VERSION 5.7 ;
  NOWIREEXTENSIONATPIN ON ;
  DIVIDERCHAR "/" ;
  BUSBITCHARS "[]" ;
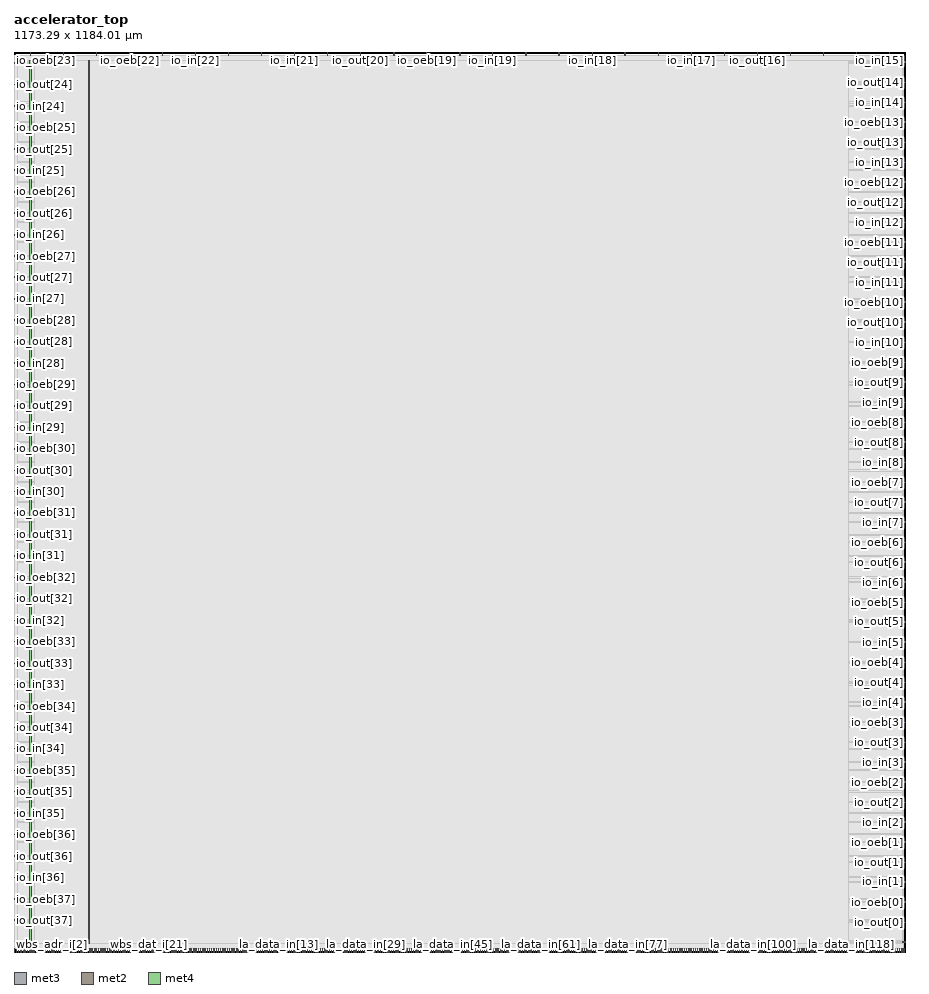
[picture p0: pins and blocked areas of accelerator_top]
MACRO accelerator_top
  CLASS BLOCK ;
  FOREIGN accelerator_top ;
  ORIGIN 0.000 0.000 ;
  SIZE 1173.290 BY 1184.010 ;
  PIN io_in[0]
    DIRECTION INPUT ;
    PORT
      LAYER met3 ;
        RECT 1169.290 12.960 1173.290 13.560 ;
    END
  END io_in[0]
  PIN io_in[10]
    DIRECTION INPUT ;
    PORT
      LAYER met3 ;
        RECT 1169.290 801.760 1173.290 802.360 ;
    END
  END io_in[10]
  PIN io_in[11]
    DIRECTION INPUT ;
    PORT
      LAYER met3 ;
        RECT 1169.290 880.640 1173.290 881.240 ;
    END
  END io_in[11]
  PIN io_in[12]
    DIRECTION INPUT ;
    PORT
      LAYER met3 ;
        RECT 1169.290 959.520 1173.290 960.120 ;
    END
  END io_in[12]
  PIN io_in[13]
    DIRECTION INPUT ;
    PORT
      LAYER met3 ;
        RECT 1169.290 1038.400 1173.290 1039.000 ;
    END
  END io_in[13]
  PIN io_in[14]
    DIRECTION INPUT ;
    PORT
      LAYER met3 ;
        RECT 1169.290 1117.280 1173.290 1117.880 ;
    END
  END io_in[14]
  PIN io_in[15]
    DIRECTION INPUT ;
    PORT
      LAYER met2 ;
        RECT 1151.470 1180.010 1151.750 1184.010 ;
    END
  END io_in[15]
  PIN io_in[16]
    DIRECTION INPUT ;
    PORT
      LAYER met2 ;
        RECT 1021.290 1180.010 1021.570 1184.010 ;
    END
  END io_in[16]
  PIN io_in[17]
    DIRECTION INPUT ;
    PORT
      LAYER met2 ;
        RECT 890.650 1180.010 890.930 1184.010 ;
    END
  END io_in[17]
  PIN io_in[18]
    DIRECTION INPUT ;
    PORT
      LAYER met2 ;
        RECT 760.470 1180.010 760.750 1184.010 ;
    END
  END io_in[18]
  PIN io_in[19]
    DIRECTION INPUT ;
    PORT
      LAYER met2 ;
        RECT 629.830 1180.010 630.110 1184.010 ;
    END
  END io_in[19]
  PIN io_in[1]
    DIRECTION INPUT ;
    PORT
      LAYER met3 ;
        RECT 1169.290 91.840 1173.290 92.440 ;
    END
  END io_in[1]
  PIN io_in[20]
    DIRECTION INPUT ;
    PORT
      LAYER met2 ;
        RECT 499.650 1180.010 499.930 1184.010 ;
    END
  END io_in[20]
  PIN io_in[21]
    DIRECTION INPUT ;
    PORT
      LAYER met2 ;
        RECT 369.010 1180.010 369.290 1184.010 ;
    END
  END io_in[21]
  PIN io_in[22]
    DIRECTION INPUT ;
    PORT
      LAYER met2 ;
        RECT 238.830 1180.010 239.110 1184.010 ;
    END
  END io_in[22]
  PIN io_in[23]
    DIRECTION INPUT ;
    PORT
      LAYER met2 ;
        RECT 108.190 1180.010 108.470 1184.010 ;
    END
  END io_in[23]
  PIN io_in[24]
    DIRECTION INPUT ;
    PORT
      LAYER met3 ;
        RECT 0.000 1112.520 4.000 1113.120 ;
    END
  END io_in[24]
  PIN io_in[25]
    DIRECTION INPUT ;
    PORT
      LAYER met3 ;
        RECT 0.000 1028.200 4.000 1028.800 ;
    END
  END io_in[25]
  PIN io_in[26]
    DIRECTION INPUT ;
    PORT
      LAYER met3 ;
        RECT 0.000 943.200 4.000 943.800 ;
    END
  END io_in[26]
  PIN io_in[27]
    DIRECTION INPUT ;
    PORT
      LAYER met3 ;
        RECT 0.000 858.880 4.000 859.480 ;
    END
  END io_in[27]
  PIN io_in[28]
    DIRECTION INPUT ;
    PORT
      LAYER met3 ;
        RECT 0.000 774.560 4.000 775.160 ;
    END
  END io_in[28]
  PIN io_in[29]
    DIRECTION INPUT ;
    PORT
      LAYER met3 ;
        RECT 0.000 689.560 4.000 690.160 ;
    END
  END io_in[29]
  PIN io_in[2]
    DIRECTION INPUT ;
    PORT
      LAYER met3 ;
        RECT 1169.290 170.720 1173.290 171.320 ;
    END
  END io_in[2]
  PIN io_in[30]
    DIRECTION INPUT ;
    PORT
      LAYER met3 ;
        RECT 0.000 605.240 4.000 605.840 ;
    END
  END io_in[30]
  PIN io_in[31]
    DIRECTION INPUT ;
    PORT
      LAYER met3 ;
        RECT 0.000 520.920 4.000 521.520 ;
    END
  END io_in[31]
  PIN io_in[32]
    DIRECTION INPUT ;
    PORT
      LAYER met3 ;
        RECT 0.000 435.920 4.000 436.520 ;
    END
  END io_in[32]
  PIN io_in[33]
    DIRECTION INPUT ;
    PORT
      LAYER met3 ;
        RECT 0.000 351.600 4.000 352.200 ;
    END
  END io_in[33]
  PIN io_in[34]
    DIRECTION INPUT ;
    PORT
      LAYER met3 ;
        RECT 0.000 267.280 4.000 267.880 ;
    END
  END io_in[34]
  PIN io_in[35]
    DIRECTION INPUT ;
    PORT
      LAYER met3 ;
        RECT 0.000 182.280 4.000 182.880 ;
    END
  END io_in[35]
  PIN io_in[36]
    DIRECTION INPUT ;
    PORT
      LAYER met3 ;
        RECT 0.000 97.960 4.000 98.560 ;
    END
  END io_in[36]
  PIN io_in[37]
    DIRECTION INPUT ;
    PORT
      LAYER met3 ;
        RECT 0.000 13.640 4.000 14.240 ;
    END
  END io_in[37]
  PIN io_in[3]
    DIRECTION INPUT ;
    PORT
      LAYER met3 ;
        RECT 1169.290 249.600 1173.290 250.200 ;
    END
  END io_in[3]
  PIN io_in[4]
    DIRECTION INPUT ;
    PORT
      LAYER met3 ;
        RECT 1169.290 328.480 1173.290 329.080 ;
    END
  END io_in[4]
  PIN io_in[5]
    DIRECTION INPUT ;
    PORT
      LAYER met3 ;
        RECT 1169.290 407.360 1173.290 407.960 ;
    END
  END io_in[5]
  PIN io_in[6]
    DIRECTION INPUT ;
    PORT
      LAYER met3 ;
        RECT 1169.290 486.240 1173.290 486.840 ;
    END
  END io_in[6]
  PIN io_in[7]
    DIRECTION INPUT ;
    PORT
      LAYER met3 ;
        RECT 1169.290 565.120 1173.290 565.720 ;
    END
  END io_in[7]
  PIN io_in[8]
    DIRECTION INPUT ;
    PORT
      LAYER met3 ;
        RECT 1169.290 644.000 1173.290 644.600 ;
    END
  END io_in[8]
  PIN io_in[9]
    DIRECTION INPUT ;
    PORT
      LAYER met3 ;
        RECT 1169.290 722.880 1173.290 723.480 ;
    END
  END io_in[9]
  PIN io_oeb[0]
    DIRECTION OUTPUT TRISTATE ;
    PORT
      LAYER met3 ;
        RECT 1169.290 65.320 1173.290 65.920 ;
    END
  END io_oeb[0]
  PIN io_oeb[10]
    DIRECTION OUTPUT TRISTATE ;
    PORT
      LAYER met3 ;
        RECT 1169.290 854.800 1173.290 855.400 ;
    END
  END io_oeb[10]
  PIN io_oeb[11]
    DIRECTION OUTPUT TRISTATE ;
    PORT
      LAYER met3 ;
        RECT 1169.290 933.680 1173.290 934.280 ;
    END
  END io_oeb[11]
  PIN io_oeb[12]
    DIRECTION OUTPUT TRISTATE ;
    PORT
      LAYER met3 ;
        RECT 1169.290 1012.560 1173.290 1013.160 ;
    END
  END io_oeb[12]
  PIN io_oeb[13]
    DIRECTION OUTPUT TRISTATE ;
    PORT
      LAYER met3 ;
        RECT 1169.290 1091.440 1173.290 1092.040 ;
    END
  END io_oeb[13]
  PIN io_oeb[14]
    DIRECTION OUTPUT TRISTATE ;
    PORT
      LAYER met3 ;
        RECT 1169.290 1170.320 1173.290 1170.920 ;
    END
  END io_oeb[14]
  PIN io_oeb[15]
    DIRECTION OUTPUT TRISTATE ;
    PORT
      LAYER met2 ;
        RECT 1064.530 1180.010 1064.810 1184.010 ;
    END
  END io_oeb[15]
  PIN io_oeb[16]
    DIRECTION OUTPUT TRISTATE ;
    PORT
      LAYER met2 ;
        RECT 934.350 1180.010 934.630 1184.010 ;
    END
  END io_oeb[16]
  PIN io_oeb[17]
    DIRECTION OUTPUT TRISTATE ;
    PORT
      LAYER met2 ;
        RECT 803.710 1180.010 803.990 1184.010 ;
    END
  END io_oeb[17]
  PIN io_oeb[18]
    DIRECTION OUTPUT TRISTATE ;
    PORT
      LAYER met2 ;
        RECT 673.530 1180.010 673.810 1184.010 ;
    END
  END io_oeb[18]
  PIN io_oeb[19]
    DIRECTION OUTPUT TRISTATE ;
    PORT
      LAYER met2 ;
        RECT 542.890 1180.010 543.170 1184.010 ;
    END
  END io_oeb[19]
  PIN io_oeb[1]
    DIRECTION OUTPUT TRISTATE ;
    PORT
      LAYER met3 ;
        RECT 1169.290 144.200 1173.290 144.800 ;
    END
  END io_oeb[1]
  PIN io_oeb[20]
    DIRECTION OUTPUT TRISTATE ;
    PORT
      LAYER met2 ;
        RECT 412.710 1180.010 412.990 1184.010 ;
    END
  END io_oeb[20]
  PIN io_oeb[21]
    DIRECTION OUTPUT TRISTATE ;
    PORT
      LAYER met2 ;
        RECT 282.070 1180.010 282.350 1184.010 ;
    END
  END io_oeb[21]
  PIN io_oeb[22]
    DIRECTION OUTPUT TRISTATE ;
    PORT
      LAYER met2 ;
        RECT 151.890 1180.010 152.170 1184.010 ;
    END
  END io_oeb[22]
  PIN io_oeb[23]
    DIRECTION OUTPUT TRISTATE ;
    PORT
      LAYER met2 ;
        RECT 21.710 1180.010 21.990 1184.010 ;
    END
  END io_oeb[23]
  PIN io_oeb[24]
    DIRECTION OUTPUT TRISTATE ;
    PORT
      LAYER met3 ;
        RECT 0.000 1168.960 4.000 1169.560 ;
    END
  END io_oeb[24]
  PIN io_oeb[25]
    DIRECTION OUTPUT TRISTATE ;
    PORT
      LAYER met3 ;
        RECT 0.000 1084.640 4.000 1085.240 ;
    END
  END io_oeb[25]
  PIN io_oeb[26]
    DIRECTION OUTPUT TRISTATE ;
    PORT
      LAYER met3 ;
        RECT 0.000 999.640 4.000 1000.240 ;
    END
  END io_oeb[26]
  PIN io_oeb[27]
    DIRECTION OUTPUT TRISTATE ;
    PORT
      LAYER met3 ;
        RECT 0.000 915.320 4.000 915.920 ;
    END
  END io_oeb[27]
  PIN io_oeb[28]
    DIRECTION OUTPUT TRISTATE ;
    PORT
      LAYER met3 ;
        RECT 0.000 831.000 4.000 831.600 ;
    END
  END io_oeb[28]
  PIN io_oeb[29]
    DIRECTION OUTPUT TRISTATE ;
    PORT
      LAYER met3 ;
        RECT 0.000 746.000 4.000 746.600 ;
    END
  END io_oeb[29]
  PIN io_oeb[2]
    DIRECTION OUTPUT TRISTATE ;
    PORT
      LAYER met3 ;
        RECT 1169.290 223.080 1173.290 223.680 ;
    END
  END io_oeb[2]
  PIN io_oeb[30]
    DIRECTION OUTPUT TRISTATE ;
    PORT
      LAYER met3 ;
        RECT 0.000 661.680 4.000 662.280 ;
    END
  END io_oeb[30]
  PIN io_oeb[31]
    DIRECTION OUTPUT TRISTATE ;
    PORT
      LAYER met3 ;
        RECT 0.000 577.360 4.000 577.960 ;
    END
  END io_oeb[31]
  PIN io_oeb[32]
    DIRECTION OUTPUT TRISTATE ;
    PORT
      LAYER met3 ;
        RECT 0.000 492.360 4.000 492.960 ;
    END
  END io_oeb[32]
  PIN io_oeb[33]
    DIRECTION OUTPUT TRISTATE ;
    PORT
      LAYER met3 ;
        RECT 0.000 408.040 4.000 408.640 ;
    END
  END io_oeb[33]
  PIN io_oeb[34]
    DIRECTION OUTPUT TRISTATE ;
    PORT
      LAYER met3 ;
        RECT 0.000 323.040 4.000 323.640 ;
    END
  END io_oeb[34]
  PIN io_oeb[35]
    DIRECTION OUTPUT TRISTATE ;
    PORT
      LAYER met3 ;
        RECT 0.000 238.720 4.000 239.320 ;
    END
  END io_oeb[35]
  PIN io_oeb[36]
    DIRECTION OUTPUT TRISTATE ;
    PORT
      LAYER met3 ;
        RECT 0.000 154.400 4.000 155.000 ;
    END
  END io_oeb[36]
  PIN io_oeb[37]
    DIRECTION OUTPUT TRISTATE ;
    PORT
      LAYER met3 ;
        RECT 0.000 69.400 4.000 70.000 ;
    END
  END io_oeb[37]
  PIN io_oeb[3]
    DIRECTION OUTPUT TRISTATE ;
    PORT
      LAYER met3 ;
        RECT 1169.290 301.960 1173.290 302.560 ;
    END
  END io_oeb[3]
  PIN io_oeb[4]
    DIRECTION OUTPUT TRISTATE ;
    PORT
      LAYER met3 ;
        RECT 1169.290 380.840 1173.290 381.440 ;
    END
  END io_oeb[4]
  PIN io_oeb[5]
    DIRECTION OUTPUT TRISTATE ;
    PORT
      LAYER met3 ;
        RECT 1169.290 459.720 1173.290 460.320 ;
    END
  END io_oeb[5]
  PIN io_oeb[6]
    DIRECTION OUTPUT TRISTATE ;
    PORT
      LAYER met3 ;
        RECT 1169.290 538.600 1173.290 539.200 ;
    END
  END io_oeb[6]
  PIN io_oeb[7]
    DIRECTION OUTPUT TRISTATE ;
    PORT
      LAYER met3 ;
        RECT 1169.290 617.480 1173.290 618.080 ;
    END
  END io_oeb[7]
  PIN io_oeb[8]
    DIRECTION OUTPUT TRISTATE ;
    PORT
      LAYER met3 ;
        RECT 1169.290 696.360 1173.290 696.960 ;
    END
  END io_oeb[8]
  PIN io_oeb[9]
    DIRECTION OUTPUT TRISTATE ;
    PORT
      LAYER met3 ;
        RECT 1169.290 775.240 1173.290 775.840 ;
    END
  END io_oeb[9]
  PIN io_out[0]
    DIRECTION OUTPUT TRISTATE ;
    PORT
      LAYER met3 ;
        RECT 1169.290 38.800 1173.290 39.400 ;
    END
  END io_out[0]
  PIN io_out[10]
    DIRECTION OUTPUT TRISTATE ;
    PORT
      LAYER met3 ;
        RECT 1169.290 828.280 1173.290 828.880 ;
    END
  END io_out[10]
  PIN io_out[11]
    DIRECTION OUTPUT TRISTATE ;
    PORT
      LAYER met3 ;
        RECT 1169.290 907.160 1173.290 907.760 ;
    END
  END io_out[11]
  PIN io_out[12]
    DIRECTION OUTPUT TRISTATE ;
    PORT
      LAYER met3 ;
        RECT 1169.290 986.040 1173.290 986.640 ;
    END
  END io_out[12]
  PIN io_out[13]
    DIRECTION OUTPUT TRISTATE ;
    PORT
      LAYER met3 ;
        RECT 1169.290 1064.920 1173.290 1065.520 ;
    END
  END io_out[13]
  PIN io_out[14]
    DIRECTION OUTPUT TRISTATE ;
    PORT
      LAYER met3 ;
        RECT 1169.290 1143.800 1173.290 1144.400 ;
    END
  END io_out[14]
  PIN io_out[15]
    DIRECTION OUTPUT TRISTATE ;
    PORT
      LAYER met2 ;
        RECT 1108.230 1180.010 1108.510 1184.010 ;
    END
  END io_out[15]
  PIN io_out[16]
    DIRECTION OUTPUT TRISTATE ;
    PORT
      LAYER met2 ;
        RECT 977.590 1180.010 977.870 1184.010 ;
    END
  END io_out[16]
  PIN io_out[17]
    DIRECTION OUTPUT TRISTATE ;
    PORT
      LAYER met2 ;
        RECT 847.410 1180.010 847.690 1184.010 ;
    END
  END io_out[17]
  PIN io_out[18]
    DIRECTION OUTPUT TRISTATE ;
    PORT
      LAYER met2 ;
        RECT 716.770 1180.010 717.050 1184.010 ;
    END
  END io_out[18]
  PIN io_out[19]
    DIRECTION OUTPUT TRISTATE ;
    PORT
      LAYER met2 ;
        RECT 586.590 1180.010 586.870 1184.010 ;
    END
  END io_out[19]
  PIN io_out[1]
    DIRECTION OUTPUT TRISTATE ;
    PORT
      LAYER met3 ;
        RECT 1169.290 117.680 1173.290 118.280 ;
    END
  END io_out[1]
  PIN io_out[20]
    DIRECTION OUTPUT TRISTATE ;
    PORT
      LAYER met2 ;
        RECT 455.950 1180.010 456.230 1184.010 ;
    END
  END io_out[20]
  PIN io_out[21]
    DIRECTION OUTPUT TRISTATE ;
    PORT
      LAYER met2 ;
        RECT 325.770 1180.010 326.050 1184.010 ;
    END
  END io_out[21]
  PIN io_out[22]
    DIRECTION OUTPUT TRISTATE ;
    PORT
      LAYER met2 ;
        RECT 195.130 1180.010 195.410 1184.010 ;
    END
  END io_out[22]
  PIN io_out[23]
    DIRECTION OUTPUT TRISTATE ;
    PORT
      LAYER met2 ;
        RECT 64.950 1180.010 65.230 1184.010 ;
    END
  END io_out[23]
  PIN io_out[24]
    DIRECTION OUTPUT TRISTATE ;
    PORT
      LAYER met3 ;
        RECT 0.000 1141.080 4.000 1141.680 ;
    END
  END io_out[24]
  PIN io_out[25]
    DIRECTION OUTPUT TRISTATE ;
    PORT
      LAYER met3 ;
        RECT 0.000 1056.080 4.000 1056.680 ;
    END
  END io_out[25]
  PIN io_out[26]
    DIRECTION OUTPUT TRISTATE ;
    PORT
      LAYER met3 ;
        RECT 0.000 971.760 4.000 972.360 ;
    END
  END io_out[26]
  PIN io_out[27]
    DIRECTION OUTPUT TRISTATE ;
    PORT
      LAYER met3 ;
        RECT 0.000 887.440 4.000 888.040 ;
    END
  END io_out[27]
  PIN io_out[28]
    DIRECTION OUTPUT TRISTATE ;
    PORT
      LAYER met3 ;
        RECT 0.000 802.440 4.000 803.040 ;
    END
  END io_out[28]
  PIN io_out[29]
    DIRECTION OUTPUT TRISTATE ;
    PORT
      LAYER met3 ;
        RECT 0.000 718.120 4.000 718.720 ;
    END
  END io_out[29]
  PIN io_out[2]
    DIRECTION OUTPUT TRISTATE ;
    PORT
      LAYER met3 ;
        RECT 1169.290 196.560 1173.290 197.160 ;
    END
  END io_out[2]
  PIN io_out[30]
    DIRECTION OUTPUT TRISTATE ;
    PORT
      LAYER met3 ;
        RECT 0.000 633.120 4.000 633.720 ;
    END
  END io_out[30]
  PIN io_out[31]
    DIRECTION OUTPUT TRISTATE ;
    PORT
      LAYER met3 ;
        RECT 0.000 548.800 4.000 549.400 ;
    END
  END io_out[31]
  PIN io_out[32]
    DIRECTION OUTPUT TRISTATE ;
    PORT
      LAYER met3 ;
        RECT 0.000 464.480 4.000 465.080 ;
    END
  END io_out[32]
  PIN io_out[33]
    DIRECTION OUTPUT TRISTATE ;
    PORT
      LAYER met3 ;
        RECT 0.000 379.480 4.000 380.080 ;
    END
  END io_out[33]
  PIN io_out[34]
    DIRECTION OUTPUT TRISTATE ;
    PORT
      LAYER met3 ;
        RECT 0.000 295.160 4.000 295.760 ;
    END
  END io_out[34]
  PIN io_out[35]
    DIRECTION OUTPUT TRISTATE ;
    PORT
      LAYER met3 ;
        RECT 0.000 210.840 4.000 211.440 ;
    END
  END io_out[35]
  PIN io_out[36]
    DIRECTION OUTPUT TRISTATE ;
    PORT
      LAYER met3 ;
        RECT 0.000 125.840 4.000 126.440 ;
    END
  END io_out[36]
  PIN io_out[37]
    DIRECTION OUTPUT TRISTATE ;
    PORT
      LAYER met3 ;
        RECT 0.000 41.520 4.000 42.120 ;
    END
  END io_out[37]
  PIN io_out[3]
    DIRECTION OUTPUT TRISTATE ;
    PORT
      LAYER met3 ;
        RECT 1169.290 275.440 1173.290 276.040 ;
    END
  END io_out[3]
  PIN io_out[4]
    DIRECTION OUTPUT TRISTATE ;
    PORT
      LAYER met3 ;
        RECT 1169.290 354.320 1173.290 354.920 ;
    END
  END io_out[4]
  PIN io_out[5]
    DIRECTION OUTPUT TRISTATE ;
    PORT
      LAYER met3 ;
        RECT 1169.290 433.880 1173.290 434.480 ;
    END
  END io_out[5]
  PIN io_out[6]
    DIRECTION OUTPUT TRISTATE ;
    PORT
      LAYER met3 ;
        RECT 1169.290 512.760 1173.290 513.360 ;
    END
  END io_out[6]
  PIN io_out[7]
    DIRECTION OUTPUT TRISTATE ;
    PORT
      LAYER met3 ;
        RECT 1169.290 591.640 1173.290 592.240 ;
    END
  END io_out[7]
  PIN io_out[8]
    DIRECTION OUTPUT TRISTATE ;
    PORT
      LAYER met3 ;
        RECT 1169.290 670.520 1173.290 671.120 ;
    END
  END io_out[8]
  PIN io_out[9]
    DIRECTION OUTPUT TRISTATE ;
    PORT
      LAYER met3 ;
        RECT 1169.290 749.400 1173.290 750.000 ;
    END
  END io_out[9]
  PIN la_data_in[0]
    DIRECTION INPUT ;
    PORT
      LAYER met2 ;
        RECT 254.470 0.000 254.750 4.000 ;
    END
  END la_data_in[0]
  PIN la_data_in[100]
    DIRECTION INPUT ;
    PORT
      LAYER met2 ;
        RECT 972.990 0.000 973.270 4.000 ;
    END
  END la_data_in[100]
  PIN la_data_in[101]
    DIRECTION INPUT ;
    PORT
      LAYER met2 ;
        RECT 980.350 0.000 980.630 4.000 ;
    END
  END la_data_in[101]
  PIN la_data_in[102]
    DIRECTION INPUT ;
    PORT
      LAYER met2 ;
        RECT 987.250 0.000 987.530 4.000 ;
    END
  END la_data_in[102]
  PIN la_data_in[103]
    DIRECTION INPUT ;
    PORT
      LAYER met2 ;
        RECT 994.610 0.000 994.890 4.000 ;
    END
  END la_data_in[103]
  PIN la_data_in[104]
    DIRECTION INPUT ;
    PORT
      LAYER met2 ;
        RECT 1001.970 0.000 1002.250 4.000 ;
    END
  END la_data_in[104]
  PIN la_data_in[105]
    DIRECTION INPUT ;
    PORT
      LAYER met2 ;
        RECT 1008.870 0.000 1009.150 4.000 ;
    END
  END la_data_in[105]
  PIN la_data_in[106]
    DIRECTION INPUT ;
    PORT
      LAYER met2 ;
        RECT 1016.230 0.000 1016.510 4.000 ;
    END
  END la_data_in[106]
  PIN la_data_in[107]
    DIRECTION INPUT ;
    PORT
      LAYER met2 ;
        RECT 1023.590 0.000 1023.870 4.000 ;
    END
  END la_data_in[107]
  PIN la_data_in[108]
    DIRECTION INPUT ;
    PORT
      LAYER met2 ;
        RECT 1030.490 0.000 1030.770 4.000 ;
    END
  END la_data_in[108]
  PIN la_data_in[109]
    DIRECTION INPUT ;
    PORT
      LAYER met2 ;
        RECT 1037.850 0.000 1038.130 4.000 ;
    END
  END la_data_in[109]
  PIN la_data_in[10]
    DIRECTION INPUT ;
    PORT
      LAYER met2 ;
        RECT 326.690 0.000 326.970 4.000 ;
    END
  END la_data_in[10]
  PIN la_data_in[110]
    DIRECTION INPUT ;
    PORT
      LAYER met2 ;
        RECT 1044.750 0.000 1045.030 4.000 ;
    END
  END la_data_in[110]
  PIN la_data_in[111]
    DIRECTION INPUT ;
    PORT
      LAYER met2 ;
        RECT 1052.110 0.000 1052.390 4.000 ;
    END
  END la_data_in[111]
  PIN la_data_in[112]
    DIRECTION INPUT ;
    PORT
      LAYER met2 ;
        RECT 1059.470 0.000 1059.750 4.000 ;
    END
  END la_data_in[112]
  PIN la_data_in[113]
    DIRECTION INPUT ;
    PORT
      LAYER met2 ;
        RECT 1066.370 0.000 1066.650 4.000 ;
    END
  END la_data_in[113]
  PIN la_data_in[114]
    DIRECTION INPUT ;
    PORT
      LAYER met2 ;
        RECT 1073.730 0.000 1074.010 4.000 ;
    END
  END la_data_in[114]
  PIN la_data_in[115]
    DIRECTION INPUT ;
    PORT
      LAYER met2 ;
        RECT 1080.630 0.000 1080.910 4.000 ;
    END
  END la_data_in[115]
  PIN la_data_in[116]
    DIRECTION INPUT ;
    PORT
      LAYER met2 ;
        RECT 1087.990 0.000 1088.270 4.000 ;
    END
  END la_data_in[116]
  PIN la_data_in[117]
    DIRECTION INPUT ;
    PORT
      LAYER met2 ;
        RECT 1095.350 0.000 1095.630 4.000 ;
    END
  END la_data_in[117]
  PIN la_data_in[118]
    DIRECTION INPUT ;
    PORT
      LAYER met2 ;
        RECT 1102.250 0.000 1102.530 4.000 ;
    END
  END la_data_in[118]
  PIN la_data_in[119]
    DIRECTION INPUT ;
    PORT
      LAYER met2 ;
        RECT 1109.610 0.000 1109.890 4.000 ;
    END
  END la_data_in[119]
  PIN la_data_in[11]
    DIRECTION INPUT ;
    PORT
      LAYER met2 ;
        RECT 333.590 0.000 333.870 4.000 ;
    END
  END la_data_in[11]
  PIN la_data_in[120]
    DIRECTION INPUT ;
    PORT
      LAYER met2 ;
        RECT 1116.970 0.000 1117.250 4.000 ;
    END
  END la_data_in[120]
  PIN la_data_in[121]
    DIRECTION INPUT ;
    PORT
      LAYER met2 ;
        RECT 1123.870 0.000 1124.150 4.000 ;
    END
  END la_data_in[121]
  PIN la_data_in[122]
    DIRECTION INPUT ;
    PORT
      LAYER met2 ;
        RECT 1131.230 0.000 1131.510 4.000 ;
    END
  END la_data_in[122]
  PIN la_data_in[123]
    DIRECTION INPUT ;
    PORT
      LAYER met2 ;
        RECT 1138.130 0.000 1138.410 4.000 ;
    END
  END la_data_in[123]
  PIN la_data_in[124]
    DIRECTION INPUT ;
    PORT
      LAYER met2 ;
        RECT 1145.490 0.000 1145.770 4.000 ;
    END
  END la_data_in[124]
  PIN la_data_in[125]
    DIRECTION INPUT ;
    PORT
      LAYER met2 ;
        RECT 1152.850 0.000 1153.130 4.000 ;
    END
  END la_data_in[125]
  PIN la_data_in[126]
    DIRECTION INPUT ;
    PORT
      LAYER met2 ;
        RECT 1159.750 0.000 1160.030 4.000 ;
    END
  END la_data_in[126]
  PIN la_data_in[127]
    DIRECTION INPUT ;
    PORT
      LAYER met2 ;
        RECT 1167.110 0.000 1167.390 4.000 ;
    END
  END la_data_in[127]
  PIN la_data_in[12]
    DIRECTION INPUT ;
    PORT
      LAYER met2 ;
        RECT 340.950 0.000 341.230 4.000 ;
    END
  END la_data_in[12]
  PIN la_data_in[13]
    DIRECTION INPUT ;
    PORT
      LAYER met2 ;
        RECT 347.850 0.000 348.130 4.000 ;
    END
  END la_data_in[13]
  PIN la_data_in[14]
    DIRECTION INPUT ;
    PORT
      LAYER met2 ;
        RECT 355.210 0.000 355.490 4.000 ;
    END
  END la_data_in[14]
  PIN la_data_in[15]
    DIRECTION INPUT ;
    PORT
      LAYER met2 ;
        RECT 362.570 0.000 362.850 4.000 ;
    END
  END la_data_in[15]
  PIN la_data_in[16]
    DIRECTION INPUT ;
    PORT
      LAYER met2 ;
        RECT 369.470 0.000 369.750 4.000 ;
    END
  END la_data_in[16]
  PIN la_data_in[17]
    DIRECTION INPUT ;
    PORT
      LAYER met2 ;
        RECT 376.830 0.000 377.110 4.000 ;
    END
  END la_data_in[17]
  PIN la_data_in[18]
    DIRECTION INPUT ;
    PORT
      LAYER met2 ;
        RECT 383.730 0.000 384.010 4.000 ;
    END
  END la_data_in[18]
  PIN la_data_in[19]
    DIRECTION INPUT ;
    PORT
      LAYER met2 ;
        RECT 391.090 0.000 391.370 4.000 ;
    END
  END la_data_in[19]
  PIN la_data_in[1]
    DIRECTION INPUT ;
    PORT
      LAYER met2 ;
        RECT 261.830 0.000 262.110 4.000 ;
    END
  END la_data_in[1]
  PIN la_data_in[20]
    DIRECTION INPUT ;
    PORT
      LAYER met2 ;
        RECT 398.450 0.000 398.730 4.000 ;
    END
  END la_data_in[20]
  PIN la_data_in[21]
    DIRECTION INPUT ;
    PORT
      LAYER met2 ;
        RECT 405.350 0.000 405.630 4.000 ;
    END
  END la_data_in[21]
  PIN la_data_in[22]
    DIRECTION INPUT ;
    PORT
      LAYER met2 ;
        RECT 412.710 0.000 412.990 4.000 ;
    END
  END la_data_in[22]
  PIN la_data_in[23]
    DIRECTION INPUT ;
    PORT
      LAYER met2 ;
        RECT 420.070 0.000 420.350 4.000 ;
    END
  END la_data_in[23]
  PIN la_data_in[24]
    DIRECTION INPUT ;
    PORT
      LAYER met2 ;
        RECT 426.970 0.000 427.250 4.000 ;
    END
  END la_data_in[24]
  PIN la_data_in[25]
    DIRECTION INPUT ;
    PORT
      LAYER met2 ;
        RECT 434.330 0.000 434.610 4.000 ;
    END
  END la_data_in[25]
  PIN la_data_in[26]
    DIRECTION INPUT ;
    PORT
      LAYER met2 ;
        RECT 441.230 0.000 441.510 4.000 ;
    END
  END la_data_in[26]
  PIN la_data_in[27]
    DIRECTION INPUT ;
    PORT
      LAYER met2 ;
        RECT 448.590 0.000 448.870 4.000 ;
    END
  END la_data_in[27]
  PIN la_data_in[28]
    DIRECTION INPUT ;
    PORT
      LAYER met2 ;
        RECT 455.950 0.000 456.230 4.000 ;
    END
  END la_data_in[28]
  PIN la_data_in[29]
    DIRECTION INPUT ;
    PORT
      LAYER met2 ;
        RECT 462.850 0.000 463.130 4.000 ;
    END
  END la_data_in[29]
  PIN la_data_in[2]
    DIRECTION INPUT ;
    PORT
      LAYER met2 ;
        RECT 269.190 0.000 269.470 4.000 ;
    END
  END la_data_in[2]
  PIN la_data_in[30]
    DIRECTION INPUT ;
    PORT
      LAYER met2 ;
        RECT 470.210 0.000 470.490 4.000 ;
    END
  END la_data_in[30]
  PIN la_data_in[31]
    DIRECTION INPUT ;
    PORT
      LAYER met2 ;
        RECT 477.570 0.000 477.850 4.000 ;
    END
  END la_data_in[31]
  PIN la_data_in[32]
    DIRECTION INPUT ;
    PORT
      LAYER met2 ;
        RECT 484.470 0.000 484.750 4.000 ;
    END
  END la_data_in[32]
  PIN la_data_in[33]
    DIRECTION INPUT ;
    PORT
      LAYER met2 ;
        RECT 491.830 0.000 492.110 4.000 ;
    END
  END la_data_in[33]
  PIN la_data_in[34]
    DIRECTION INPUT ;
    PORT
      LAYER met2 ;
        RECT 498.730 0.000 499.010 4.000 ;
    END
  END la_data_in[34]
  PIN la_data_in[35]
    DIRECTION INPUT ;
    PORT
      LAYER met2 ;
        RECT 506.090 0.000 506.370 4.000 ;
    END
  END la_data_in[35]
  PIN la_data_in[36]
    DIRECTION INPUT ;
    PORT
      LAYER met2 ;
        RECT 513.450 0.000 513.730 4.000 ;
    END
  END la_data_in[36]
  PIN la_data_in[37]
    DIRECTION INPUT ;
    PORT
      LAYER met2 ;
        RECT 520.350 0.000 520.630 4.000 ;
    END
  END la_data_in[37]
  PIN la_data_in[38]
    DIRECTION INPUT ;
    PORT
      LAYER met2 ;
        RECT 527.710 0.000 527.990 4.000 ;
    END
  END la_data_in[38]
  PIN la_data_in[39]
    DIRECTION INPUT ;
    PORT
      LAYER met2 ;
        RECT 534.610 0.000 534.890 4.000 ;
    END
  END la_data_in[39]
  PIN la_data_in[3]
    DIRECTION INPUT ;
    PORT
      LAYER met2 ;
        RECT 276.090 0.000 276.370 4.000 ;
    END
  END la_data_in[3]
  PIN la_data_in[40]
    DIRECTION INPUT ;
    PORT
      LAYER met2 ;
        RECT 541.970 0.000 542.250 4.000 ;
    END
  END la_data_in[40]
  PIN la_data_in[41]
    DIRECTION INPUT ;
    PORT
      LAYER met2 ;
        RECT 549.330 0.000 549.610 4.000 ;
    END
  END la_data_in[41]
  PIN la_data_in[42]
    DIRECTION INPUT ;
    PORT
      LAYER met2 ;
        RECT 556.230 0.000 556.510 4.000 ;
    END
  END la_data_in[42]
  PIN la_data_in[43]
    DIRECTION INPUT ;
    PORT
      LAYER met2 ;
        RECT 563.590 0.000 563.870 4.000 ;
    END
  END la_data_in[43]
  PIN la_data_in[44]
    DIRECTION INPUT ;
    PORT
      LAYER met2 ;
        RECT 570.950 0.000 571.230 4.000 ;
    END
  END la_data_in[44]
  PIN la_data_in[45]
    DIRECTION INPUT ;
    PORT
      LAYER met2 ;
        RECT 577.850 0.000 578.130 4.000 ;
    END
  END la_data_in[45]
  PIN la_data_in[46]
    DIRECTION INPUT ;
    PORT
      LAYER met2 ;
        RECT 585.210 0.000 585.490 4.000 ;
    END
  END la_data_in[46]
  PIN la_data_in[47]
    DIRECTION INPUT ;
    PORT
      LAYER met2 ;
        RECT 592.110 0.000 592.390 4.000 ;
    END
  END la_data_in[47]
  PIN la_data_in[48]
    DIRECTION INPUT ;
    PORT
      LAYER met2 ;
        RECT 599.470 0.000 599.750 4.000 ;
    END
  END la_data_in[48]
  PIN la_data_in[49]
    DIRECTION INPUT ;
    PORT
      LAYER met2 ;
        RECT 606.830 0.000 607.110 4.000 ;
    END
  END la_data_in[49]
  PIN la_data_in[4]
    DIRECTION INPUT ;
    PORT
      LAYER met2 ;
        RECT 283.450 0.000 283.730 4.000 ;
    END
  END la_data_in[4]
  PIN la_data_in[50]
    DIRECTION INPUT ;
    PORT
      LAYER met2 ;
        RECT 613.730 0.000 614.010 4.000 ;
    END
  END la_data_in[50]
  PIN la_data_in[51]
    DIRECTION INPUT ;
    PORT
      LAYER met2 ;
        RECT 621.090 0.000 621.370 4.000 ;
    END
  END la_data_in[51]
  PIN la_data_in[52]
    DIRECTION INPUT ;
    PORT
      LAYER met2 ;
        RECT 628.450 0.000 628.730 4.000 ;
    END
  END la_data_in[52]
  PIN la_data_in[53]
    DIRECTION INPUT ;
    PORT
      LAYER met2 ;
        RECT 635.350 0.000 635.630 4.000 ;
    END
  END la_data_in[53]
  PIN la_data_in[54]
    DIRECTION INPUT ;
    PORT
      LAYER met2 ;
        RECT 642.710 0.000 642.990 4.000 ;
    END
  END la_data_in[54]
  PIN la_data_in[55]
    DIRECTION INPUT ;
    PORT
      LAYER met2 ;
        RECT 649.610 0.000 649.890 4.000 ;
    END
  END la_data_in[55]
  PIN la_data_in[56]
    DIRECTION INPUT ;
    PORT
      LAYER met2 ;
        RECT 656.970 0.000 657.250 4.000 ;
    END
  END la_data_in[56]
  PIN la_data_in[57]
    DIRECTION INPUT ;
    PORT
      LAYER met2 ;
        RECT 664.330 0.000 664.610 4.000 ;
    END
  END la_data_in[57]
  PIN la_data_in[58]
    DIRECTION INPUT ;
    PORT
      LAYER met2 ;
        RECT 671.230 0.000 671.510 4.000 ;
    END
  END la_data_in[58]
  PIN la_data_in[59]
    DIRECTION INPUT ;
    PORT
      LAYER met2 ;
        RECT 678.590 0.000 678.870 4.000 ;
    END
  END la_data_in[59]
  PIN la_data_in[5]
    DIRECTION INPUT ;
    PORT
      LAYER met2 ;
        RECT 290.350 0.000 290.630 4.000 ;
    END
  END la_data_in[5]
  PIN la_data_in[60]
    DIRECTION INPUT ;
    PORT
      LAYER met2 ;
        RECT 685.490 0.000 685.770 4.000 ;
    END
  END la_data_in[60]
  PIN la_data_in[61]
    DIRECTION INPUT ;
    PORT
      LAYER met2 ;
        RECT 692.850 0.000 693.130 4.000 ;
    END
  END la_data_in[61]
  PIN la_data_in[62]
    DIRECTION INPUT ;
    PORT
      LAYER met2 ;
        RECT 700.210 0.000 700.490 4.000 ;
    END
  END la_data_in[62]
  PIN la_data_in[63]
    DIRECTION INPUT ;
    PORT
      LAYER met2 ;
        RECT 707.110 0.000 707.390 4.000 ;
    END
  END la_data_in[63]
  PIN la_data_in[64]
    DIRECTION INPUT ;
    PORT
      LAYER met2 ;
        RECT 714.470 0.000 714.750 4.000 ;
    END
  END la_data_in[64]
  PIN la_data_in[65]
    DIRECTION INPUT ;
    PORT
      LAYER met2 ;
        RECT 721.830 0.000 722.110 4.000 ;
    END
  END la_data_in[65]
  PIN la_data_in[66]
    DIRECTION INPUT ;
    PORT
      LAYER met2 ;
        RECT 728.730 0.000 729.010 4.000 ;
    END
  END la_data_in[66]
  PIN la_data_in[67]
    DIRECTION INPUT ;
    PORT
      LAYER met2 ;
        RECT 736.090 0.000 736.370 4.000 ;
    END
  END la_data_in[67]
  PIN la_data_in[68]
    DIRECTION INPUT ;
    PORT
      LAYER met2 ;
        RECT 742.990 0.000 743.270 4.000 ;
    END
  END la_data_in[68]
  PIN la_data_in[69]
    DIRECTION INPUT ;
    PORT
      LAYER met2 ;
        RECT 750.350 0.000 750.630 4.000 ;
    END
  END la_data_in[69]
  PIN la_data_in[6]
    DIRECTION INPUT ;
    PORT
      LAYER met2 ;
        RECT 297.710 0.000 297.990 4.000 ;
    END
  END la_data_in[6]
  PIN la_data_in[70]
    DIRECTION INPUT ;
    PORT
      LAYER met2 ;
        RECT 757.710 0.000 757.990 4.000 ;
    END
  END la_data_in[70]
  PIN la_data_in[71]
    DIRECTION INPUT ;
    PORT
      LAYER met2 ;
        RECT 764.610 0.000 764.890 4.000 ;
    END
  END la_data_in[71]
  PIN la_data_in[72]
    DIRECTION INPUT ;
    PORT
      LAYER met2 ;
        RECT 771.970 0.000 772.250 4.000 ;
    END
  END la_data_in[72]
  PIN la_data_in[73]
    DIRECTION INPUT ;
    PORT
      LAYER met2 ;
        RECT 778.870 0.000 779.150 4.000 ;
    END
  END la_data_in[73]
  PIN la_data_in[74]
    DIRECTION INPUT ;
    PORT
      LAYER met2 ;
        RECT 786.230 0.000 786.510 4.000 ;
    END
  END la_data_in[74]
  PIN la_data_in[75]
    DIRECTION INPUT ;
    PORT
      LAYER met2 ;
        RECT 793.590 0.000 793.870 4.000 ;
    END
  END la_data_in[75]
  PIN la_data_in[76]
    DIRECTION INPUT ;
    PORT
      LAYER met2 ;
        RECT 800.490 0.000 800.770 4.000 ;
    END
  END la_data_in[76]
  PIN la_data_in[77]
    DIRECTION INPUT ;
    PORT
      LAYER met2 ;
        RECT 807.850 0.000 808.130 4.000 ;
    END
  END la_data_in[77]
  PIN la_data_in[78]
    DIRECTION INPUT ;
    PORT
      LAYER met2 ;
        RECT 815.210 0.000 815.490 4.000 ;
    END
  END la_data_in[78]
  PIN la_data_in[79]
    DIRECTION INPUT ;
    PORT
      LAYER met2 ;
        RECT 822.110 0.000 822.390 4.000 ;
    END
  END la_data_in[79]
  PIN la_data_in[7]
    DIRECTION INPUT ;
    PORT
      LAYER met2 ;
        RECT 305.070 0.000 305.350 4.000 ;
    END
  END la_data_in[7]
  PIN la_data_in[80]
    DIRECTION INPUT ;
    PORT
      LAYER met2 ;
        RECT 829.470 0.000 829.750 4.000 ;
    END
  END la_data_in[80]
  PIN la_data_in[81]
    DIRECTION INPUT ;
    PORT
      LAYER met2 ;
        RECT 836.370 0.000 836.650 4.000 ;
    END
  END la_data_in[81]
  PIN la_data_in[82]
    DIRECTION INPUT ;
    PORT
      LAYER met2 ;
        RECT 843.730 0.000 844.010 4.000 ;
    END
  END la_data_in[82]
  PIN la_data_in[83]
    DIRECTION INPUT ;
    PORT
      LAYER met2 ;
        RECT 851.090 0.000 851.370 4.000 ;
    END
  END la_data_in[83]
  PIN la_data_in[84]
    DIRECTION INPUT ;
    PORT
      LAYER met2 ;
        RECT 857.990 0.000 858.270 4.000 ;
    END
  END la_data_in[84]
  PIN la_data_in[85]
    DIRECTION INPUT ;
    PORT
      LAYER met2 ;
        RECT 865.350 0.000 865.630 4.000 ;
    END
  END la_data_in[85]
  PIN la_data_in[86]
    DIRECTION INPUT ;
    PORT
      LAYER met2 ;
        RECT 872.710 0.000 872.990 4.000 ;
    END
  END la_data_in[86]
  PIN la_data_in[87]
    DIRECTION INPUT ;
    PORT
      LAYER met2 ;
        RECT 879.610 0.000 879.890 4.000 ;
    END
  END la_data_in[87]
  PIN la_data_in[88]
    DIRECTION INPUT ;
    PORT
      LAYER met2 ;
        RECT 886.970 0.000 887.250 4.000 ;
    END
  END la_data_in[88]
  PIN la_data_in[89]
    DIRECTION INPUT ;
    PORT
      LAYER met2 ;
        RECT 893.870 0.000 894.150 4.000 ;
    END
  END la_data_in[89]
  PIN la_data_in[8]
    DIRECTION INPUT ;
    PORT
      LAYER met2 ;
        RECT 311.970 0.000 312.250 4.000 ;
    END
  END la_data_in[8]
  PIN la_data_in[90]
    DIRECTION INPUT ;
    PORT
      LAYER met2 ;
        RECT 901.230 0.000 901.510 4.000 ;
    END
  END la_data_in[90]
  PIN la_data_in[91]
    DIRECTION INPUT ;
    PORT
      LAYER met2 ;
        RECT 908.590 0.000 908.870 4.000 ;
    END
  END la_data_in[91]
  PIN la_data_in[92]
    DIRECTION INPUT ;
    PORT
      LAYER met2 ;
        RECT 915.490 0.000 915.770 4.000 ;
    END
  END la_data_in[92]
  PIN la_data_in[93]
    DIRECTION INPUT ;
    PORT
      LAYER met2 ;
        RECT 922.850 0.000 923.130 4.000 ;
    END
  END la_data_in[93]
  PIN la_data_in[94]
    DIRECTION INPUT ;
    PORT
      LAYER met2 ;
        RECT 929.750 0.000 930.030 4.000 ;
    END
  END la_data_in[94]
  PIN la_data_in[95]
    DIRECTION INPUT ;
    PORT
      LAYER met2 ;
        RECT 937.110 0.000 937.390 4.000 ;
    END
  END la_data_in[95]
  PIN la_data_in[96]
    DIRECTION INPUT ;
    PORT
      LAYER met2 ;
        RECT 944.470 0.000 944.750 4.000 ;
    END
  END la_data_in[96]
  PIN la_data_in[97]
    DIRECTION INPUT ;
    PORT
      LAYER met2 ;
        RECT 951.370 0.000 951.650 4.000 ;
    END
  END la_data_in[97]
  PIN la_data_in[98]
    DIRECTION INPUT ;
    PORT
      LAYER met2 ;
        RECT 958.730 0.000 959.010 4.000 ;
    END
  END la_data_in[98]
  PIN la_data_in[99]
    DIRECTION INPUT ;
    PORT
      LAYER met2 ;
        RECT 966.090 0.000 966.370 4.000 ;
    END
  END la_data_in[99]
  PIN la_data_in[9]
    DIRECTION INPUT ;
    PORT
      LAYER met2 ;
        RECT 319.330 0.000 319.610 4.000 ;
    END
  END la_data_in[9]
  PIN la_data_out[0]
    DIRECTION OUTPUT TRISTATE ;
    PORT
      LAYER met2 ;
        RECT 257.230 0.000 257.510 4.000 ;
    END
  END la_data_out[0]
  PIN la_data_out[100]
    DIRECTION OUTPUT TRISTATE ;
    PORT
      LAYER met2 ;
        RECT 975.290 0.000 975.570 4.000 ;
    END
  END la_data_out[100]
  PIN la_data_out[101]
    DIRECTION OUTPUT TRISTATE ;
    PORT
      LAYER met2 ;
        RECT 982.650 0.000 982.930 4.000 ;
    END
  END la_data_out[101]
  PIN la_data_out[102]
    DIRECTION OUTPUT TRISTATE ;
    PORT
      LAYER met2 ;
        RECT 990.010 0.000 990.290 4.000 ;
    END
  END la_data_out[102]
  PIN la_data_out[103]
    DIRECTION OUTPUT TRISTATE ;
    PORT
      LAYER met2 ;
        RECT 996.910 0.000 997.190 4.000 ;
    END
  END la_data_out[103]
  PIN la_data_out[104]
    DIRECTION OUTPUT TRISTATE ;
    PORT
      LAYER met2 ;
        RECT 1004.270 0.000 1004.550 4.000 ;
    END
  END la_data_out[104]
  PIN la_data_out[105]
    DIRECTION OUTPUT TRISTATE ;
    PORT
      LAYER met2 ;
        RECT 1011.170 0.000 1011.450 4.000 ;
    END
  END la_data_out[105]
  PIN la_data_out[106]
    DIRECTION OUTPUT TRISTATE ;
    PORT
      LAYER met2 ;
        RECT 1018.530 0.000 1018.810 4.000 ;
    END
  END la_data_out[106]
  PIN la_data_out[107]
    DIRECTION OUTPUT TRISTATE ;
    PORT
      LAYER met2 ;
        RECT 1025.890 0.000 1026.170 4.000 ;
    END
  END la_data_out[107]
  PIN la_data_out[108]
    DIRECTION OUTPUT TRISTATE ;
    PORT
      LAYER met2 ;
        RECT 1032.790 0.000 1033.070 4.000 ;
    END
  END la_data_out[108]
  PIN la_data_out[109]
    DIRECTION OUTPUT TRISTATE ;
    PORT
      LAYER met2 ;
        RECT 1040.150 0.000 1040.430 4.000 ;
    END
  END la_data_out[109]
  PIN la_data_out[10]
    DIRECTION OUTPUT TRISTATE ;
    PORT
      LAYER met2 ;
        RECT 328.990 0.000 329.270 4.000 ;
    END
  END la_data_out[10]
  PIN la_data_out[110]
    DIRECTION OUTPUT TRISTATE ;
    PORT
      LAYER met2 ;
        RECT 1047.510 0.000 1047.790 4.000 ;
    END
  END la_data_out[110]
  PIN la_data_out[111]
    DIRECTION OUTPUT TRISTATE ;
    PORT
      LAYER met2 ;
        RECT 1054.410 0.000 1054.690 4.000 ;
    END
  END la_data_out[111]
  PIN la_data_out[112]
    DIRECTION OUTPUT TRISTATE ;
    PORT
      LAYER met2 ;
        RECT 1061.770 0.000 1062.050 4.000 ;
    END
  END la_data_out[112]
  PIN la_data_out[113]
    DIRECTION OUTPUT TRISTATE ;
    PORT
      LAYER met2 ;
        RECT 1068.670 0.000 1068.950 4.000 ;
    END
  END la_data_out[113]
  PIN la_data_out[114]
    DIRECTION OUTPUT TRISTATE ;
    PORT
      LAYER met2 ;
        RECT 1076.030 0.000 1076.310 4.000 ;
    END
  END la_data_out[114]
  PIN la_data_out[115]
    DIRECTION OUTPUT TRISTATE ;
    PORT
      LAYER met2 ;
        RECT 1083.390 0.000 1083.670 4.000 ;
    END
  END la_data_out[115]
  PIN la_data_out[116]
    DIRECTION OUTPUT TRISTATE ;
    PORT
      LAYER met2 ;
        RECT 1090.290 0.000 1090.570 4.000 ;
    END
  END la_data_out[116]
  PIN la_data_out[117]
    DIRECTION OUTPUT TRISTATE ;
    PORT
      LAYER met2 ;
        RECT 1097.650 0.000 1097.930 4.000 ;
    END
  END la_data_out[117]
  PIN la_data_out[118]
    DIRECTION OUTPUT TRISTATE ;
    PORT
      LAYER met2 ;
        RECT 1105.010 0.000 1105.290 4.000 ;
    END
  END la_data_out[118]
  PIN la_data_out[119]
    DIRECTION OUTPUT TRISTATE ;
    PORT
      LAYER met2 ;
        RECT 1111.910 0.000 1112.190 4.000 ;
    END
  END la_data_out[119]
  PIN la_data_out[11]
    DIRECTION OUTPUT TRISTATE ;
    PORT
      LAYER met2 ;
        RECT 335.890 0.000 336.170 4.000 ;
    END
  END la_data_out[11]
  PIN la_data_out[120]
    DIRECTION OUTPUT TRISTATE ;
    PORT
      LAYER met2 ;
        RECT 1119.270 0.000 1119.550 4.000 ;
    END
  END la_data_out[120]
  PIN la_data_out[121]
    DIRECTION OUTPUT TRISTATE ;
    PORT
      LAYER met2 ;
        RECT 1126.170 0.000 1126.450 4.000 ;
    END
  END la_data_out[121]
  PIN la_data_out[122]
    DIRECTION OUTPUT TRISTATE ;
    PORT
      LAYER met2 ;
        RECT 1133.530 0.000 1133.810 4.000 ;
    END
  END la_data_out[122]
  PIN la_data_out[123]
    DIRECTION OUTPUT TRISTATE ;
    PORT
      LAYER met2 ;
        RECT 1140.890 0.000 1141.170 4.000 ;
    END
  END la_data_out[123]
  PIN la_data_out[124]
    DIRECTION OUTPUT TRISTATE ;
    PORT
      LAYER met2 ;
        RECT 1147.790 0.000 1148.070 4.000 ;
    END
  END la_data_out[124]
  PIN la_data_out[125]
    DIRECTION OUTPUT TRISTATE ;
    PORT
      LAYER met2 ;
        RECT 1155.150 0.000 1155.430 4.000 ;
    END
  END la_data_out[125]
  PIN la_data_out[126]
    DIRECTION OUTPUT TRISTATE ;
    PORT
      LAYER met2 ;
        RECT 1162.050 0.000 1162.330 4.000 ;
    END
  END la_data_out[126]
  PIN la_data_out[127]
    DIRECTION OUTPUT TRISTATE ;
    PORT
      LAYER met2 ;
        RECT 1169.410 0.000 1169.690 4.000 ;
    END
  END la_data_out[127]
  PIN la_data_out[12]
    DIRECTION OUTPUT TRISTATE ;
    PORT
      LAYER met2 ;
        RECT 343.250 0.000 343.530 4.000 ;
    END
  END la_data_out[12]
  PIN la_data_out[13]
    DIRECTION OUTPUT TRISTATE ;
    PORT
      LAYER met2 ;
        RECT 350.610 0.000 350.890 4.000 ;
    END
  END la_data_out[13]
  PIN la_data_out[14]
    DIRECTION OUTPUT TRISTATE ;
    PORT
      LAYER met2 ;
        RECT 357.510 0.000 357.790 4.000 ;
    END
  END la_data_out[14]
  PIN la_data_out[15]
    DIRECTION OUTPUT TRISTATE ;
    PORT
      LAYER met2 ;
        RECT 364.870 0.000 365.150 4.000 ;
    END
  END la_data_out[15]
  PIN la_data_out[16]
    DIRECTION OUTPUT TRISTATE ;
    PORT
      LAYER met2 ;
        RECT 371.770 0.000 372.050 4.000 ;
    END
  END la_data_out[16]
  PIN la_data_out[17]
    DIRECTION OUTPUT TRISTATE ;
    PORT
      LAYER met2 ;
        RECT 379.130 0.000 379.410 4.000 ;
    END
  END la_data_out[17]
  PIN la_data_out[18]
    DIRECTION OUTPUT TRISTATE ;
    PORT
      LAYER met2 ;
        RECT 386.490 0.000 386.770 4.000 ;
    END
  END la_data_out[18]
  PIN la_data_out[19]
    DIRECTION OUTPUT TRISTATE ;
    PORT
      LAYER met2 ;
        RECT 393.390 0.000 393.670 4.000 ;
    END
  END la_data_out[19]
  PIN la_data_out[1]
    DIRECTION OUTPUT TRISTATE ;
    PORT
      LAYER met2 ;
        RECT 264.130 0.000 264.410 4.000 ;
    END
  END la_data_out[1]
  PIN la_data_out[20]
    DIRECTION OUTPUT TRISTATE ;
    PORT
      LAYER met2 ;
        RECT 400.750 0.000 401.030 4.000 ;
    END
  END la_data_out[20]
  PIN la_data_out[21]
    DIRECTION OUTPUT TRISTATE ;
    PORT
      LAYER met2 ;
        RECT 408.110 0.000 408.390 4.000 ;
    END
  END la_data_out[21]
  PIN la_data_out[22]
    DIRECTION OUTPUT TRISTATE ;
    PORT
      LAYER met2 ;
        RECT 415.010 0.000 415.290 4.000 ;
    END
  END la_data_out[22]
  PIN la_data_out[23]
    DIRECTION OUTPUT TRISTATE ;
    PORT
      LAYER met2 ;
        RECT 422.370 0.000 422.650 4.000 ;
    END
  END la_data_out[23]
  PIN la_data_out[24]
    DIRECTION OUTPUT TRISTATE ;
    PORT
      LAYER met2 ;
        RECT 429.270 0.000 429.550 4.000 ;
    END
  END la_data_out[24]
  PIN la_data_out[25]
    DIRECTION OUTPUT TRISTATE ;
    PORT
      LAYER met2 ;
        RECT 436.630 0.000 436.910 4.000 ;
    END
  END la_data_out[25]
  PIN la_data_out[26]
    DIRECTION OUTPUT TRISTATE ;
    PORT
      LAYER met2 ;
        RECT 443.990 0.000 444.270 4.000 ;
    END
  END la_data_out[26]
  PIN la_data_out[27]
    DIRECTION OUTPUT TRISTATE ;
    PORT
      LAYER met2 ;
        RECT 450.890 0.000 451.170 4.000 ;
    END
  END la_data_out[27]
  PIN la_data_out[28]
    DIRECTION OUTPUT TRISTATE ;
    PORT
      LAYER met2 ;
        RECT 458.250 0.000 458.530 4.000 ;
    END
  END la_data_out[28]
  PIN la_data_out[29]
    DIRECTION OUTPUT TRISTATE ;
    PORT
      LAYER met2 ;
        RECT 465.150 0.000 465.430 4.000 ;
    END
  END la_data_out[29]
  PIN la_data_out[2]
    DIRECTION OUTPUT TRISTATE ;
    PORT
      LAYER met2 ;
        RECT 271.490 0.000 271.770 4.000 ;
    END
  END la_data_out[2]
  PIN la_data_out[30]
    DIRECTION OUTPUT TRISTATE ;
    PORT
      LAYER met2 ;
        RECT 472.510 0.000 472.790 4.000 ;
    END
  END la_data_out[30]
  PIN la_data_out[31]
    DIRECTION OUTPUT TRISTATE ;
    PORT
      LAYER met2 ;
        RECT 479.870 0.000 480.150 4.000 ;
    END
  END la_data_out[31]
  PIN la_data_out[32]
    DIRECTION OUTPUT TRISTATE ;
    PORT
      LAYER met2 ;
        RECT 486.770 0.000 487.050 4.000 ;
    END
  END la_data_out[32]
  PIN la_data_out[33]
    DIRECTION OUTPUT TRISTATE ;
    PORT
      LAYER met2 ;
        RECT 494.130 0.000 494.410 4.000 ;
    END
  END la_data_out[33]
  PIN la_data_out[34]
    DIRECTION OUTPUT TRISTATE ;
    PORT
      LAYER met2 ;
        RECT 501.490 0.000 501.770 4.000 ;
    END
  END la_data_out[34]
  PIN la_data_out[35]
    DIRECTION OUTPUT TRISTATE ;
    PORT
      LAYER met2 ;
        RECT 508.390 0.000 508.670 4.000 ;
    END
  END la_data_out[35]
  PIN la_data_out[36]
    DIRECTION OUTPUT TRISTATE ;
    PORT
      LAYER met2 ;
        RECT 515.750 0.000 516.030 4.000 ;
    END
  END la_data_out[36]
  PIN la_data_out[37]
    DIRECTION OUTPUT TRISTATE ;
    PORT
      LAYER met2 ;
        RECT 522.650 0.000 522.930 4.000 ;
    END
  END la_data_out[37]
  PIN la_data_out[38]
    DIRECTION OUTPUT TRISTATE ;
    PORT
      LAYER met2 ;
        RECT 530.010 0.000 530.290 4.000 ;
    END
  END la_data_out[38]
  PIN la_data_out[39]
    DIRECTION OUTPUT TRISTATE ;
    PORT
      LAYER met2 ;
        RECT 537.370 0.000 537.650 4.000 ;
    END
  END la_data_out[39]
  PIN la_data_out[3]
    DIRECTION OUTPUT TRISTATE ;
    PORT
      LAYER met2 ;
        RECT 278.390 0.000 278.670 4.000 ;
    END
  END la_data_out[3]
  PIN la_data_out[40]
    DIRECTION OUTPUT TRISTATE ;
    PORT
      LAYER met2 ;
        RECT 544.270 0.000 544.550 4.000 ;
    END
  END la_data_out[40]
  PIN la_data_out[41]
    DIRECTION OUTPUT TRISTATE ;
    PORT
      LAYER met2 ;
        RECT 551.630 0.000 551.910 4.000 ;
    END
  END la_data_out[41]
  PIN la_data_out[42]
    DIRECTION OUTPUT TRISTATE ;
    PORT
      LAYER met2 ;
        RECT 558.990 0.000 559.270 4.000 ;
    END
  END la_data_out[42]
  PIN la_data_out[43]
    DIRECTION OUTPUT TRISTATE ;
    PORT
      LAYER met2 ;
        RECT 565.890 0.000 566.170 4.000 ;
    END
  END la_data_out[43]
  PIN la_data_out[44]
    DIRECTION OUTPUT TRISTATE ;
    PORT
      LAYER met2 ;
        RECT 573.250 0.000 573.530 4.000 ;
    END
  END la_data_out[44]
  PIN la_data_out[45]
    DIRECTION OUTPUT TRISTATE ;
    PORT
      LAYER met2 ;
        RECT 580.150 0.000 580.430 4.000 ;
    END
  END la_data_out[45]
  PIN la_data_out[46]
    DIRECTION OUTPUT TRISTATE ;
    PORT
      LAYER met2 ;
        RECT 587.510 0.000 587.790 4.000 ;
    END
  END la_data_out[46]
  PIN la_data_out[47]
    DIRECTION OUTPUT TRISTATE ;
    PORT
      LAYER met2 ;
        RECT 594.870 0.000 595.150 4.000 ;
    END
  END la_data_out[47]
  PIN la_data_out[48]
    DIRECTION OUTPUT TRISTATE ;
    PORT
      LAYER met2 ;
        RECT 601.770 0.000 602.050 4.000 ;
    END
  END la_data_out[48]
  PIN la_data_out[49]
    DIRECTION OUTPUT TRISTATE ;
    PORT
      LAYER met2 ;
        RECT 609.130 0.000 609.410 4.000 ;
    END
  END la_data_out[49]
  PIN la_data_out[4]
    DIRECTION OUTPUT TRISTATE ;
    PORT
      LAYER met2 ;
        RECT 285.750 0.000 286.030 4.000 ;
    END
  END la_data_out[4]
  PIN la_data_out[50]
    DIRECTION OUTPUT TRISTATE ;
    PORT
      LAYER met2 ;
        RECT 616.030 0.000 616.310 4.000 ;
    END
  END la_data_out[50]
  PIN la_data_out[51]
    DIRECTION OUTPUT TRISTATE ;
    PORT
      LAYER met2 ;
        RECT 623.390 0.000 623.670 4.000 ;
    END
  END la_data_out[51]
  PIN la_data_out[52]
    DIRECTION OUTPUT TRISTATE ;
    PORT
      LAYER met2 ;
        RECT 630.750 0.000 631.030 4.000 ;
    END
  END la_data_out[52]
  PIN la_data_out[53]
    DIRECTION OUTPUT TRISTATE ;
    PORT
      LAYER met2 ;
        RECT 637.650 0.000 637.930 4.000 ;
    END
  END la_data_out[53]
  PIN la_data_out[54]
    DIRECTION OUTPUT TRISTATE ;
    PORT
      LAYER met2 ;
        RECT 645.010 0.000 645.290 4.000 ;
    END
  END la_data_out[54]
  PIN la_data_out[55]
    DIRECTION OUTPUT TRISTATE ;
    PORT
      LAYER met2 ;
        RECT 652.370 0.000 652.650 4.000 ;
    END
  END la_data_out[55]
  PIN la_data_out[56]
    DIRECTION OUTPUT TRISTATE ;
    PORT
      LAYER met2 ;
        RECT 659.270 0.000 659.550 4.000 ;
    END
  END la_data_out[56]
  PIN la_data_out[57]
    DIRECTION OUTPUT TRISTATE ;
    PORT
      LAYER met2 ;
        RECT 666.630 0.000 666.910 4.000 ;
    END
  END la_data_out[57]
  PIN la_data_out[58]
    DIRECTION OUTPUT TRISTATE ;
    PORT
      LAYER met2 ;
        RECT 673.530 0.000 673.810 4.000 ;
    END
  END la_data_out[58]
  PIN la_data_out[59]
    DIRECTION OUTPUT TRISTATE ;
    PORT
      LAYER met2 ;
        RECT 680.890 0.000 681.170 4.000 ;
    END
  END la_data_out[59]
  PIN la_data_out[5]
    DIRECTION OUTPUT TRISTATE ;
    PORT
      LAYER met2 ;
        RECT 293.110 0.000 293.390 4.000 ;
    END
  END la_data_out[5]
  PIN la_data_out[60]
    DIRECTION OUTPUT TRISTATE ;
    PORT
      LAYER met2 ;
        RECT 688.250 0.000 688.530 4.000 ;
    END
  END la_data_out[60]
  PIN la_data_out[61]
    DIRECTION OUTPUT TRISTATE ;
    PORT
      LAYER met2 ;
        RECT 695.150 0.000 695.430 4.000 ;
    END
  END la_data_out[61]
  PIN la_data_out[62]
    DIRECTION OUTPUT TRISTATE ;
    PORT
      LAYER met2 ;
        RECT 702.510 0.000 702.790 4.000 ;
    END
  END la_data_out[62]
  PIN la_data_out[63]
    DIRECTION OUTPUT TRISTATE ;
    PORT
      LAYER met2 ;
        RECT 709.870 0.000 710.150 4.000 ;
    END
  END la_data_out[63]
  PIN la_data_out[64]
    DIRECTION OUTPUT TRISTATE ;
    PORT
      LAYER met2 ;
        RECT 716.770 0.000 717.050 4.000 ;
    END
  END la_data_out[64]
  PIN la_data_out[65]
    DIRECTION OUTPUT TRISTATE ;
    PORT
      LAYER met2 ;
        RECT 724.130 0.000 724.410 4.000 ;
    END
  END la_data_out[65]
  PIN la_data_out[66]
    DIRECTION OUTPUT TRISTATE ;
    PORT
      LAYER met2 ;
        RECT 731.030 0.000 731.310 4.000 ;
    END
  END la_data_out[66]
  PIN la_data_out[67]
    DIRECTION OUTPUT TRISTATE ;
    PORT
      LAYER met2 ;
        RECT 738.390 0.000 738.670 4.000 ;
    END
  END la_data_out[67]
  PIN la_data_out[68]
    DIRECTION OUTPUT TRISTATE ;
    PORT
      LAYER met2 ;
        RECT 745.750 0.000 746.030 4.000 ;
    END
  END la_data_out[68]
  PIN la_data_out[69]
    DIRECTION OUTPUT TRISTATE ;
    PORT
      LAYER met2 ;
        RECT 752.650 0.000 752.930 4.000 ;
    END
  END la_data_out[69]
  PIN la_data_out[6]
    DIRECTION OUTPUT TRISTATE ;
    PORT
      LAYER met2 ;
        RECT 300.010 0.000 300.290 4.000 ;
    END
  END la_data_out[6]
  PIN la_data_out[70]
    DIRECTION OUTPUT TRISTATE ;
    PORT
      LAYER met2 ;
        RECT 760.010 0.000 760.290 4.000 ;
    END
  END la_data_out[70]
  PIN la_data_out[71]
    DIRECTION OUTPUT TRISTATE ;
    PORT
      LAYER met2 ;
        RECT 766.910 0.000 767.190 4.000 ;
    END
  END la_data_out[71]
  PIN la_data_out[72]
    DIRECTION OUTPUT TRISTATE ;
    PORT
      LAYER met2 ;
        RECT 774.270 0.000 774.550 4.000 ;
    END
  END la_data_out[72]
  PIN la_data_out[73]
    DIRECTION OUTPUT TRISTATE ;
    PORT
      LAYER met2 ;
        RECT 781.630 0.000 781.910 4.000 ;
    END
  END la_data_out[73]
  PIN la_data_out[74]
    DIRECTION OUTPUT TRISTATE ;
    PORT
      LAYER met2 ;
        RECT 788.530 0.000 788.810 4.000 ;
    END
  END la_data_out[74]
  PIN la_data_out[75]
    DIRECTION OUTPUT TRISTATE ;
    PORT
      LAYER met2 ;
        RECT 795.890 0.000 796.170 4.000 ;
    END
  END la_data_out[75]
  PIN la_data_out[76]
    DIRECTION OUTPUT TRISTATE ;
    PORT
      LAYER met2 ;
        RECT 803.250 0.000 803.530 4.000 ;
    END
  END la_data_out[76]
  PIN la_data_out[77]
    DIRECTION OUTPUT TRISTATE ;
    PORT
      LAYER met2 ;
        RECT 810.150 0.000 810.430 4.000 ;
    END
  END la_data_out[77]
  PIN la_data_out[78]
    DIRECTION OUTPUT TRISTATE ;
    PORT
      LAYER met2 ;
        RECT 817.510 0.000 817.790 4.000 ;
    END
  END la_data_out[78]
  PIN la_data_out[79]
    DIRECTION OUTPUT TRISTATE ;
    PORT
      LAYER met2 ;
        RECT 824.410 0.000 824.690 4.000 ;
    END
  END la_data_out[79]
  PIN la_data_out[7]
    DIRECTION OUTPUT TRISTATE ;
    PORT
      LAYER met2 ;
        RECT 307.370 0.000 307.650 4.000 ;
    END
  END la_data_out[7]
  PIN la_data_out[80]
    DIRECTION OUTPUT TRISTATE ;
    PORT
      LAYER met2 ;
        RECT 831.770 0.000 832.050 4.000 ;
    END
  END la_data_out[80]
  PIN la_data_out[81]
    DIRECTION OUTPUT TRISTATE ;
    PORT
      LAYER met2 ;
        RECT 839.130 0.000 839.410 4.000 ;
    END
  END la_data_out[81]
  PIN la_data_out[82]
    DIRECTION OUTPUT TRISTATE ;
    PORT
      LAYER met2 ;
        RECT 846.030 0.000 846.310 4.000 ;
    END
  END la_data_out[82]
  PIN la_data_out[83]
    DIRECTION OUTPUT TRISTATE ;
    PORT
      LAYER met2 ;
        RECT 853.390 0.000 853.670 4.000 ;
    END
  END la_data_out[83]
  PIN la_data_out[84]
    DIRECTION OUTPUT TRISTATE ;
    PORT
      LAYER met2 ;
        RECT 860.290 0.000 860.570 4.000 ;
    END
  END la_data_out[84]
  PIN la_data_out[85]
    DIRECTION OUTPUT TRISTATE ;
    PORT
      LAYER met2 ;
        RECT 867.650 0.000 867.930 4.000 ;
    END
  END la_data_out[85]
  PIN la_data_out[86]
    DIRECTION OUTPUT TRISTATE ;
    PORT
      LAYER met2 ;
        RECT 875.010 0.000 875.290 4.000 ;
    END
  END la_data_out[86]
  PIN la_data_out[87]
    DIRECTION OUTPUT TRISTATE ;
    PORT
      LAYER met2 ;
        RECT 881.910 0.000 882.190 4.000 ;
    END
  END la_data_out[87]
  PIN la_data_out[88]
    DIRECTION OUTPUT TRISTATE ;
    PORT
      LAYER met2 ;
        RECT 889.270 0.000 889.550 4.000 ;
    END
  END la_data_out[88]
  PIN la_data_out[89]
    DIRECTION OUTPUT TRISTATE ;
    PORT
      LAYER met2 ;
        RECT 896.630 0.000 896.910 4.000 ;
    END
  END la_data_out[89]
  PIN la_data_out[8]
    DIRECTION OUTPUT TRISTATE ;
    PORT
      LAYER met2 ;
        RECT 314.730 0.000 315.010 4.000 ;
    END
  END la_data_out[8]
  PIN la_data_out[90]
    DIRECTION OUTPUT TRISTATE ;
    PORT
      LAYER met2 ;
        RECT 903.530 0.000 903.810 4.000 ;
    END
  END la_data_out[90]
  PIN la_data_out[91]
    DIRECTION OUTPUT TRISTATE ;
    PORT
      LAYER met2 ;
        RECT 910.890 0.000 911.170 4.000 ;
    END
  END la_data_out[91]
  PIN la_data_out[92]
    DIRECTION OUTPUT TRISTATE ;
    PORT
      LAYER met2 ;
        RECT 917.790 0.000 918.070 4.000 ;
    END
  END la_data_out[92]
  PIN la_data_out[93]
    DIRECTION OUTPUT TRISTATE ;
    PORT
      LAYER met2 ;
        RECT 925.150 0.000 925.430 4.000 ;
    END
  END la_data_out[93]
  PIN la_data_out[94]
    DIRECTION OUTPUT TRISTATE ;
    PORT
      LAYER met2 ;
        RECT 932.510 0.000 932.790 4.000 ;
    END
  END la_data_out[94]
  PIN la_data_out[95]
    DIRECTION OUTPUT TRISTATE ;
    PORT
      LAYER met2 ;
        RECT 939.410 0.000 939.690 4.000 ;
    END
  END la_data_out[95]
  PIN la_data_out[96]
    DIRECTION OUTPUT TRISTATE ;
    PORT
      LAYER met2 ;
        RECT 946.770 0.000 947.050 4.000 ;
    END
  END la_data_out[96]
  PIN la_data_out[97]
    DIRECTION OUTPUT TRISTATE ;
    PORT
      LAYER met2 ;
        RECT 954.130 0.000 954.410 4.000 ;
    END
  END la_data_out[97]
  PIN la_data_out[98]
    DIRECTION OUTPUT TRISTATE ;
    PORT
      LAYER met2 ;
        RECT 961.030 0.000 961.310 4.000 ;
    END
  END la_data_out[98]
  PIN la_data_out[99]
    DIRECTION OUTPUT TRISTATE ;
    PORT
      LAYER met2 ;
        RECT 968.390 0.000 968.670 4.000 ;
    END
  END la_data_out[99]
  PIN la_data_out[9]
    DIRECTION OUTPUT TRISTATE ;
    PORT
      LAYER met2 ;
        RECT 321.630 0.000 321.910 4.000 ;
    END
  END la_data_out[9]
  PIN la_oen[0]
    DIRECTION INPUT ;
    PORT
      LAYER met2 ;
        RECT 259.530 0.000 259.810 4.000 ;
    END
  END la_oen[0]
  PIN la_oen[100]
    DIRECTION INPUT ;
    PORT
      LAYER met2 ;
        RECT 978.050 0.000 978.330 4.000 ;
    END
  END la_oen[100]
  PIN la_oen[101]
    DIRECTION INPUT ;
    PORT
      LAYER met2 ;
        RECT 984.950 0.000 985.230 4.000 ;
    END
  END la_oen[101]
  PIN la_oen[102]
    DIRECTION INPUT ;
    PORT
      LAYER met2 ;
        RECT 992.310 0.000 992.590 4.000 ;
    END
  END la_oen[102]
  PIN la_oen[103]
    DIRECTION INPUT ;
    PORT
      LAYER met2 ;
        RECT 999.210 0.000 999.490 4.000 ;
    END
  END la_oen[103]
  PIN la_oen[104]
    DIRECTION INPUT ;
    PORT
      LAYER met2 ;
        RECT 1006.570 0.000 1006.850 4.000 ;
    END
  END la_oen[104]
  PIN la_oen[105]
    DIRECTION INPUT ;
    PORT
      LAYER met2 ;
        RECT 1013.930 0.000 1014.210 4.000 ;
    END
  END la_oen[105]
  PIN la_oen[106]
    DIRECTION INPUT ;
    PORT
      LAYER met2 ;
        RECT 1020.830 0.000 1021.110 4.000 ;
    END
  END la_oen[106]
  PIN la_oen[107]
    DIRECTION INPUT ;
    PORT
      LAYER met2 ;
        RECT 1028.190 0.000 1028.470 4.000 ;
    END
  END la_oen[107]
  PIN la_oen[108]
    DIRECTION INPUT ;
    PORT
      LAYER met2 ;
        RECT 1035.550 0.000 1035.830 4.000 ;
    END
  END la_oen[108]
  PIN la_oen[109]
    DIRECTION INPUT ;
    PORT
      LAYER met2 ;
        RECT 1042.450 0.000 1042.730 4.000 ;
    END
  END la_oen[109]
  PIN la_oen[10]
    DIRECTION INPUT ;
    PORT
      LAYER met2 ;
        RECT 331.290 0.000 331.570 4.000 ;
    END
  END la_oen[10]
  PIN la_oen[110]
    DIRECTION INPUT ;
    PORT
      LAYER met2 ;
        RECT 1049.810 0.000 1050.090 4.000 ;
    END
  END la_oen[110]
  PIN la_oen[111]
    DIRECTION INPUT ;
    PORT
      LAYER met2 ;
        RECT 1056.710 0.000 1056.990 4.000 ;
    END
  END la_oen[111]
  PIN la_oen[112]
    DIRECTION INPUT ;
    PORT
      LAYER met2 ;
        RECT 1064.070 0.000 1064.350 4.000 ;
    END
  END la_oen[112]
  PIN la_oen[113]
    DIRECTION INPUT ;
    PORT
      LAYER met2 ;
        RECT 1071.430 0.000 1071.710 4.000 ;
    END
  END la_oen[113]
  PIN la_oen[114]
    DIRECTION INPUT ;
    PORT
      LAYER met2 ;
        RECT 1078.330 0.000 1078.610 4.000 ;
    END
  END la_oen[114]
  PIN la_oen[115]
    DIRECTION INPUT ;
    PORT
      LAYER met2 ;
        RECT 1085.690 0.000 1085.970 4.000 ;
    END
  END la_oen[115]
  PIN la_oen[116]
    DIRECTION INPUT ;
    PORT
      LAYER met2 ;
        RECT 1092.590 0.000 1092.870 4.000 ;
    END
  END la_oen[116]
  PIN la_oen[117]
    DIRECTION INPUT ;
    PORT
      LAYER met2 ;
        RECT 1099.950 0.000 1100.230 4.000 ;
    END
  END la_oen[117]
  PIN la_oen[118]
    DIRECTION INPUT ;
    PORT
      LAYER met2 ;
        RECT 1107.310 0.000 1107.590 4.000 ;
    END
  END la_oen[118]
  PIN la_oen[119]
    DIRECTION INPUT ;
    PORT
      LAYER met2 ;
        RECT 1114.210 0.000 1114.490 4.000 ;
    END
  END la_oen[119]
  PIN la_oen[11]
    DIRECTION INPUT ;
    PORT
      LAYER met2 ;
        RECT 338.650 0.000 338.930 4.000 ;
    END
  END la_oen[11]
  PIN la_oen[120]
    DIRECTION INPUT ;
    PORT
      LAYER met2 ;
        RECT 1121.570 0.000 1121.850 4.000 ;
    END
  END la_oen[120]
  PIN la_oen[121]
    DIRECTION INPUT ;
    PORT
      LAYER met2 ;
        RECT 1128.930 0.000 1129.210 4.000 ;
    END
  END la_oen[121]
  PIN la_oen[122]
    DIRECTION INPUT ;
    PORT
      LAYER met2 ;
        RECT 1135.830 0.000 1136.110 4.000 ;
    END
  END la_oen[122]
  PIN la_oen[123]
    DIRECTION INPUT ;
    PORT
      LAYER met2 ;
        RECT 1143.190 0.000 1143.470 4.000 ;
    END
  END la_oen[123]
  PIN la_oen[124]
    DIRECTION INPUT ;
    PORT
      LAYER met2 ;
        RECT 1150.090 0.000 1150.370 4.000 ;
    END
  END la_oen[124]
  PIN la_oen[125]
    DIRECTION INPUT ;
    PORT
      LAYER met2 ;
        RECT 1157.450 0.000 1157.730 4.000 ;
    END
  END la_oen[125]
  PIN la_oen[126]
    DIRECTION INPUT ;
    PORT
      LAYER met2 ;
        RECT 1164.810 0.000 1165.090 4.000 ;
    END
  END la_oen[126]
  PIN la_oen[127]
    DIRECTION INPUT ;
    PORT
      LAYER met2 ;
        RECT 1171.710 0.000 1171.990 4.000 ;
    END
  END la_oen[127]
  PIN la_oen[12]
    DIRECTION INPUT ;
    PORT
      LAYER met2 ;
        RECT 345.550 0.000 345.830 4.000 ;
    END
  END la_oen[12]
  PIN la_oen[13]
    DIRECTION INPUT ;
    PORT
      LAYER met2 ;
        RECT 352.910 0.000 353.190 4.000 ;
    END
  END la_oen[13]
  PIN la_oen[14]
    DIRECTION INPUT ;
    PORT
      LAYER met2 ;
        RECT 359.810 0.000 360.090 4.000 ;
    END
  END la_oen[14]
  PIN la_oen[15]
    DIRECTION INPUT ;
    PORT
      LAYER met2 ;
        RECT 367.170 0.000 367.450 4.000 ;
    END
  END la_oen[15]
  PIN la_oen[16]
    DIRECTION INPUT ;
    PORT
      LAYER met2 ;
        RECT 374.530 0.000 374.810 4.000 ;
    END
  END la_oen[16]
  PIN la_oen[17]
    DIRECTION INPUT ;
    PORT
      LAYER met2 ;
        RECT 381.430 0.000 381.710 4.000 ;
    END
  END la_oen[17]
  PIN la_oen[18]
    DIRECTION INPUT ;
    PORT
      LAYER met2 ;
        RECT 388.790 0.000 389.070 4.000 ;
    END
  END la_oen[18]
  PIN la_oen[19]
    DIRECTION INPUT ;
    PORT
      LAYER met2 ;
        RECT 396.150 0.000 396.430 4.000 ;
    END
  END la_oen[19]
  PIN la_oen[1]
    DIRECTION INPUT ;
    PORT
      LAYER met2 ;
        RECT 266.430 0.000 266.710 4.000 ;
    END
  END la_oen[1]
  PIN la_oen[20]
    DIRECTION INPUT ;
    PORT
      LAYER met2 ;
        RECT 403.050 0.000 403.330 4.000 ;
    END
  END la_oen[20]
  PIN la_oen[21]
    DIRECTION INPUT ;
    PORT
      LAYER met2 ;
        RECT 410.410 0.000 410.690 4.000 ;
    END
  END la_oen[21]
  PIN la_oen[22]
    DIRECTION INPUT ;
    PORT
      LAYER met2 ;
        RECT 417.310 0.000 417.590 4.000 ;
    END
  END la_oen[22]
  PIN la_oen[23]
    DIRECTION INPUT ;
    PORT
      LAYER met2 ;
        RECT 424.670 0.000 424.950 4.000 ;
    END
  END la_oen[23]
  PIN la_oen[24]
    DIRECTION INPUT ;
    PORT
      LAYER met2 ;
        RECT 432.030 0.000 432.310 4.000 ;
    END
  END la_oen[24]
  PIN la_oen[25]
    DIRECTION INPUT ;
    PORT
      LAYER met2 ;
        RECT 438.930 0.000 439.210 4.000 ;
    END
  END la_oen[25]
  PIN la_oen[26]
    DIRECTION INPUT ;
    PORT
      LAYER met2 ;
        RECT 446.290 0.000 446.570 4.000 ;
    END
  END la_oen[26]
  PIN la_oen[27]
    DIRECTION INPUT ;
    PORT
      LAYER met2 ;
        RECT 453.190 0.000 453.470 4.000 ;
    END
  END la_oen[27]
  PIN la_oen[28]
    DIRECTION INPUT ;
    PORT
      LAYER met2 ;
        RECT 460.550 0.000 460.830 4.000 ;
    END
  END la_oen[28]
  PIN la_oen[29]
    DIRECTION INPUT ;
    PORT
      LAYER met2 ;
        RECT 467.910 0.000 468.190 4.000 ;
    END
  END la_oen[29]
  PIN la_oen[2]
    DIRECTION INPUT ;
    PORT
      LAYER met2 ;
        RECT 273.790 0.000 274.070 4.000 ;
    END
  END la_oen[2]
  PIN la_oen[30]
    DIRECTION INPUT ;
    PORT
      LAYER met2 ;
        RECT 474.810 0.000 475.090 4.000 ;
    END
  END la_oen[30]
  PIN la_oen[31]
    DIRECTION INPUT ;
    PORT
      LAYER met2 ;
        RECT 482.170 0.000 482.450 4.000 ;
    END
  END la_oen[31]
  PIN la_oen[32]
    DIRECTION INPUT ;
    PORT
      LAYER met2 ;
        RECT 489.530 0.000 489.810 4.000 ;
    END
  END la_oen[32]
  PIN la_oen[33]
    DIRECTION INPUT ;
    PORT
      LAYER met2 ;
        RECT 496.430 0.000 496.710 4.000 ;
    END
  END la_oen[33]
  PIN la_oen[34]
    DIRECTION INPUT ;
    PORT
      LAYER met2 ;
        RECT 503.790 0.000 504.070 4.000 ;
    END
  END la_oen[34]
  PIN la_oen[35]
    DIRECTION INPUT ;
    PORT
      LAYER met2 ;
        RECT 510.690 0.000 510.970 4.000 ;
    END
  END la_oen[35]
  PIN la_oen[36]
    DIRECTION INPUT ;
    PORT
      LAYER met2 ;
        RECT 518.050 0.000 518.330 4.000 ;
    END
  END la_oen[36]
  PIN la_oen[37]
    DIRECTION INPUT ;
    PORT
      LAYER met2 ;
        RECT 525.410 0.000 525.690 4.000 ;
    END
  END la_oen[37]
  PIN la_oen[38]
    DIRECTION INPUT ;
    PORT
      LAYER met2 ;
        RECT 532.310 0.000 532.590 4.000 ;
    END
  END la_oen[38]
  PIN la_oen[39]
    DIRECTION INPUT ;
    PORT
      LAYER met2 ;
        RECT 539.670 0.000 539.950 4.000 ;
    END
  END la_oen[39]
  PIN la_oen[3]
    DIRECTION INPUT ;
    PORT
      LAYER met2 ;
        RECT 281.150 0.000 281.430 4.000 ;
    END
  END la_oen[3]
  PIN la_oen[40]
    DIRECTION INPUT ;
    PORT
      LAYER met2 ;
        RECT 546.570 0.000 546.850 4.000 ;
    END
  END la_oen[40]
  PIN la_oen[41]
    DIRECTION INPUT ;
    PORT
      LAYER met2 ;
        RECT 553.930 0.000 554.210 4.000 ;
    END
  END la_oen[41]
  PIN la_oen[42]
    DIRECTION INPUT ;
    PORT
      LAYER met2 ;
        RECT 561.290 0.000 561.570 4.000 ;
    END
  END la_oen[42]
  PIN la_oen[43]
    DIRECTION INPUT ;
    PORT
      LAYER met2 ;
        RECT 568.190 0.000 568.470 4.000 ;
    END
  END la_oen[43]
  PIN la_oen[44]
    DIRECTION INPUT ;
    PORT
      LAYER met2 ;
        RECT 575.550 0.000 575.830 4.000 ;
    END
  END la_oen[44]
  PIN la_oen[45]
    DIRECTION INPUT ;
    PORT
      LAYER met2 ;
        RECT 582.910 0.000 583.190 4.000 ;
    END
  END la_oen[45]
  PIN la_oen[46]
    DIRECTION INPUT ;
    PORT
      LAYER met2 ;
        RECT 589.810 0.000 590.090 4.000 ;
    END
  END la_oen[46]
  PIN la_oen[47]
    DIRECTION INPUT ;
    PORT
      LAYER met2 ;
        RECT 597.170 0.000 597.450 4.000 ;
    END
  END la_oen[47]
  PIN la_oen[48]
    DIRECTION INPUT ;
    PORT
      LAYER met2 ;
        RECT 604.070 0.000 604.350 4.000 ;
    END
  END la_oen[48]
  PIN la_oen[49]
    DIRECTION INPUT ;
    PORT
      LAYER met2 ;
        RECT 611.430 0.000 611.710 4.000 ;
    END
  END la_oen[49]
  PIN la_oen[4]
    DIRECTION INPUT ;
    PORT
      LAYER met2 ;
        RECT 288.050 0.000 288.330 4.000 ;
    END
  END la_oen[4]
  PIN la_oen[50]
    DIRECTION INPUT ;
    PORT
      LAYER met2 ;
        RECT 618.790 0.000 619.070 4.000 ;
    END
  END la_oen[50]
  PIN la_oen[51]
    DIRECTION INPUT ;
    PORT
      LAYER met2 ;
        RECT 625.690 0.000 625.970 4.000 ;
    END
  END la_oen[51]
  PIN la_oen[52]
    DIRECTION INPUT ;
    PORT
      LAYER met2 ;
        RECT 633.050 0.000 633.330 4.000 ;
    END
  END la_oen[52]
  PIN la_oen[53]
    DIRECTION INPUT ;
    PORT
      LAYER met2 ;
        RECT 640.410 0.000 640.690 4.000 ;
    END
  END la_oen[53]
  PIN la_oen[54]
    DIRECTION INPUT ;
    PORT
      LAYER met2 ;
        RECT 647.310 0.000 647.590 4.000 ;
    END
  END la_oen[54]
  PIN la_oen[55]
    DIRECTION INPUT ;
    PORT
      LAYER met2 ;
        RECT 654.670 0.000 654.950 4.000 ;
    END
  END la_oen[55]
  PIN la_oen[56]
    DIRECTION INPUT ;
    PORT
      LAYER met2 ;
        RECT 661.570 0.000 661.850 4.000 ;
    END
  END la_oen[56]
  PIN la_oen[57]
    DIRECTION INPUT ;
    PORT
      LAYER met2 ;
        RECT 668.930 0.000 669.210 4.000 ;
    END
  END la_oen[57]
  PIN la_oen[58]
    DIRECTION INPUT ;
    PORT
      LAYER met2 ;
        RECT 676.290 0.000 676.570 4.000 ;
    END
  END la_oen[58]
  PIN la_oen[59]
    DIRECTION INPUT ;
    PORT
      LAYER met2 ;
        RECT 683.190 0.000 683.470 4.000 ;
    END
  END la_oen[59]
  PIN la_oen[5]
    DIRECTION INPUT ;
    PORT
      LAYER met2 ;
        RECT 295.410 0.000 295.690 4.000 ;
    END
  END la_oen[5]
  PIN la_oen[60]
    DIRECTION INPUT ;
    PORT
      LAYER met2 ;
        RECT 690.550 0.000 690.830 4.000 ;
    END
  END la_oen[60]
  PIN la_oen[61]
    DIRECTION INPUT ;
    PORT
      LAYER met2 ;
        RECT 697.450 0.000 697.730 4.000 ;
    END
  END la_oen[61]
  PIN la_oen[62]
    DIRECTION INPUT ;
    PORT
      LAYER met2 ;
        RECT 704.810 0.000 705.090 4.000 ;
    END
  END la_oen[62]
  PIN la_oen[63]
    DIRECTION INPUT ;
    PORT
      LAYER met2 ;
        RECT 712.170 0.000 712.450 4.000 ;
    END
  END la_oen[63]
  PIN la_oen[64]
    DIRECTION INPUT ;
    PORT
      LAYER met2 ;
        RECT 719.070 0.000 719.350 4.000 ;
    END
  END la_oen[64]
  PIN la_oen[65]
    DIRECTION INPUT ;
    PORT
      LAYER met2 ;
        RECT 726.430 0.000 726.710 4.000 ;
    END
  END la_oen[65]
  PIN la_oen[66]
    DIRECTION INPUT ;
    PORT
      LAYER met2 ;
        RECT 733.790 0.000 734.070 4.000 ;
    END
  END la_oen[66]
  PIN la_oen[67]
    DIRECTION INPUT ;
    PORT
      LAYER met2 ;
        RECT 740.690 0.000 740.970 4.000 ;
    END
  END la_oen[67]
  PIN la_oen[68]
    DIRECTION INPUT ;
    PORT
      LAYER met2 ;
        RECT 748.050 0.000 748.330 4.000 ;
    END
  END la_oen[68]
  PIN la_oen[69]
    DIRECTION INPUT ;
    PORT
      LAYER met2 ;
        RECT 754.950 0.000 755.230 4.000 ;
    END
  END la_oen[69]
  PIN la_oen[6]
    DIRECTION INPUT ;
    PORT
      LAYER met2 ;
        RECT 302.310 0.000 302.590 4.000 ;
    END
  END la_oen[6]
  PIN la_oen[70]
    DIRECTION INPUT ;
    PORT
      LAYER met2 ;
        RECT 762.310 0.000 762.590 4.000 ;
    END
  END la_oen[70]
  PIN la_oen[71]
    DIRECTION INPUT ;
    PORT
      LAYER met2 ;
        RECT 769.670 0.000 769.950 4.000 ;
    END
  END la_oen[71]
  PIN la_oen[72]
    DIRECTION INPUT ;
    PORT
      LAYER met2 ;
        RECT 776.570 0.000 776.850 4.000 ;
    END
  END la_oen[72]
  PIN la_oen[73]
    DIRECTION INPUT ;
    PORT
      LAYER met2 ;
        RECT 783.930 0.000 784.210 4.000 ;
    END
  END la_oen[73]
  PIN la_oen[74]
    DIRECTION INPUT ;
    PORT
      LAYER met2 ;
        RECT 791.290 0.000 791.570 4.000 ;
    END
  END la_oen[74]
  PIN la_oen[75]
    DIRECTION INPUT ;
    PORT
      LAYER met2 ;
        RECT 798.190 0.000 798.470 4.000 ;
    END
  END la_oen[75]
  PIN la_oen[76]
    DIRECTION INPUT ;
    PORT
      LAYER met2 ;
        RECT 805.550 0.000 805.830 4.000 ;
    END
  END la_oen[76]
  PIN la_oen[77]
    DIRECTION INPUT ;
    PORT
      LAYER met2 ;
        RECT 812.450 0.000 812.730 4.000 ;
    END
  END la_oen[77]
  PIN la_oen[78]
    DIRECTION INPUT ;
    PORT
      LAYER met2 ;
        RECT 819.810 0.000 820.090 4.000 ;
    END
  END la_oen[78]
  PIN la_oen[79]
    DIRECTION INPUT ;
    PORT
      LAYER met2 ;
        RECT 827.170 0.000 827.450 4.000 ;
    END
  END la_oen[79]
  PIN la_oen[7]
    DIRECTION INPUT ;
    PORT
      LAYER met2 ;
        RECT 309.670 0.000 309.950 4.000 ;
    END
  END la_oen[7]
  PIN la_oen[80]
    DIRECTION INPUT ;
    PORT
      LAYER met2 ;
        RECT 834.070 0.000 834.350 4.000 ;
    END
  END la_oen[80]
  PIN la_oen[81]
    DIRECTION INPUT ;
    PORT
      LAYER met2 ;
        RECT 841.430 0.000 841.710 4.000 ;
    END
  END la_oen[81]
  PIN la_oen[82]
    DIRECTION INPUT ;
    PORT
      LAYER met2 ;
        RECT 848.330 0.000 848.610 4.000 ;
    END
  END la_oen[82]
  PIN la_oen[83]
    DIRECTION INPUT ;
    PORT
      LAYER met2 ;
        RECT 855.690 0.000 855.970 4.000 ;
    END
  END la_oen[83]
  PIN la_oen[84]
    DIRECTION INPUT ;
    PORT
      LAYER met2 ;
        RECT 863.050 0.000 863.330 4.000 ;
    END
  END la_oen[84]
  PIN la_oen[85]
    DIRECTION INPUT ;
    PORT
      LAYER met2 ;
        RECT 869.950 0.000 870.230 4.000 ;
    END
  END la_oen[85]
  PIN la_oen[86]
    DIRECTION INPUT ;
    PORT
      LAYER met2 ;
        RECT 877.310 0.000 877.590 4.000 ;
    END
  END la_oen[86]
  PIN la_oen[87]
    DIRECTION INPUT ;
    PORT
      LAYER met2 ;
        RECT 884.670 0.000 884.950 4.000 ;
    END
  END la_oen[87]
  PIN la_oen[88]
    DIRECTION INPUT ;
    PORT
      LAYER met2 ;
        RECT 891.570 0.000 891.850 4.000 ;
    END
  END la_oen[88]
  PIN la_oen[89]
    DIRECTION INPUT ;
    PORT
      LAYER met2 ;
        RECT 898.930 0.000 899.210 4.000 ;
    END
  END la_oen[89]
  PIN la_oen[8]
    DIRECTION INPUT ;
    PORT
      LAYER met2 ;
        RECT 317.030 0.000 317.310 4.000 ;
    END
  END la_oen[8]
  PIN la_oen[90]
    DIRECTION INPUT ;
    PORT
      LAYER met2 ;
        RECT 905.830 0.000 906.110 4.000 ;
    END
  END la_oen[90]
  PIN la_oen[91]
    DIRECTION INPUT ;
    PORT
      LAYER met2 ;
        RECT 913.190 0.000 913.470 4.000 ;
    END
  END la_oen[91]
  PIN la_oen[92]
    DIRECTION INPUT ;
    PORT
      LAYER met2 ;
        RECT 920.550 0.000 920.830 4.000 ;
    END
  END la_oen[92]
  PIN la_oen[93]
    DIRECTION INPUT ;
    PORT
      LAYER met2 ;
        RECT 927.450 0.000 927.730 4.000 ;
    END
  END la_oen[93]
  PIN la_oen[94]
    DIRECTION INPUT ;
    PORT
      LAYER met2 ;
        RECT 934.810 0.000 935.090 4.000 ;
    END
  END la_oen[94]
  PIN la_oen[95]
    DIRECTION INPUT ;
    PORT
      LAYER met2 ;
        RECT 942.170 0.000 942.450 4.000 ;
    END
  END la_oen[95]
  PIN la_oen[96]
    DIRECTION INPUT ;
    PORT
      LAYER met2 ;
        RECT 949.070 0.000 949.350 4.000 ;
    END
  END la_oen[96]
  PIN la_oen[97]
    DIRECTION INPUT ;
    PORT
      LAYER met2 ;
        RECT 956.430 0.000 956.710 4.000 ;
    END
  END la_oen[97]
  PIN la_oen[98]
    DIRECTION INPUT ;
    PORT
      LAYER met2 ;
        RECT 963.330 0.000 963.610 4.000 ;
    END
  END la_oen[98]
  PIN la_oen[99]
    DIRECTION INPUT ;
    PORT
      LAYER met2 ;
        RECT 970.690 0.000 970.970 4.000 ;
    END
  END la_oen[99]
  PIN la_oen[9]
    DIRECTION INPUT ;
    PORT
      LAYER met2 ;
        RECT 323.930 0.000 324.210 4.000 ;
    END
  END la_oen[9]
  PIN wb_clk_i
    DIRECTION INPUT ;
    PORT
      LAYER met2 ;
        RECT 1.010 0.000 1.290 4.000 ;
    END
  END wb_clk_i
  PIN wb_rst_i
    DIRECTION INPUT ;
    PORT
      LAYER met2 ;
        RECT 3.310 0.000 3.590 4.000 ;
    END
  END wb_rst_i
  PIN wbs_ack_o
    DIRECTION OUTPUT TRISTATE ;
    PORT
      LAYER met2 ;
        RECT 5.610 0.000 5.890 4.000 ;
    END
  END wbs_ack_o
  PIN wbs_adr_i[0]
    DIRECTION INPUT ;
    PORT
      LAYER met2 ;
        RECT 15.270 0.000 15.550 4.000 ;
    END
  END wbs_adr_i[0]
  PIN wbs_adr_i[10]
    DIRECTION INPUT ;
    PORT
      LAYER met2 ;
        RECT 96.690 0.000 96.970 4.000 ;
    END
  END wbs_adr_i[10]
  PIN wbs_adr_i[11]
    DIRECTION INPUT ;
    PORT
      LAYER met2 ;
        RECT 103.590 0.000 103.870 4.000 ;
    END
  END wbs_adr_i[11]
  PIN wbs_adr_i[12]
    DIRECTION INPUT ;
    PORT
      LAYER met2 ;
        RECT 110.950 0.000 111.230 4.000 ;
    END
  END wbs_adr_i[12]
  PIN wbs_adr_i[13]
    DIRECTION INPUT ;
    PORT
      LAYER met2 ;
        RECT 118.310 0.000 118.590 4.000 ;
    END
  END wbs_adr_i[13]
  PIN wbs_adr_i[14]
    DIRECTION INPUT ;
    PORT
      LAYER met2 ;
        RECT 125.210 0.000 125.490 4.000 ;
    END
  END wbs_adr_i[14]
  PIN wbs_adr_i[15]
    DIRECTION INPUT ;
    PORT
      LAYER met2 ;
        RECT 132.570 0.000 132.850 4.000 ;
    END
  END wbs_adr_i[15]
  PIN wbs_adr_i[16]
    DIRECTION INPUT ;
    PORT
      LAYER met2 ;
        RECT 139.470 0.000 139.750 4.000 ;
    END
  END wbs_adr_i[16]
  PIN wbs_adr_i[17]
    DIRECTION INPUT ;
    PORT
      LAYER met2 ;
        RECT 146.830 0.000 147.110 4.000 ;
    END
  END wbs_adr_i[17]
  PIN wbs_adr_i[18]
    DIRECTION INPUT ;
    PORT
      LAYER met2 ;
        RECT 154.190 0.000 154.470 4.000 ;
    END
  END wbs_adr_i[18]
  PIN wbs_adr_i[19]
    DIRECTION INPUT ;
    PORT
      LAYER met2 ;
        RECT 161.090 0.000 161.370 4.000 ;
    END
  END wbs_adr_i[19]
  PIN wbs_adr_i[1]
    DIRECTION INPUT ;
    PORT
      LAYER met2 ;
        RECT 24.930 0.000 25.210 4.000 ;
    END
  END wbs_adr_i[1]
  PIN wbs_adr_i[20]
    DIRECTION INPUT ;
    PORT
      LAYER met2 ;
        RECT 168.450 0.000 168.730 4.000 ;
    END
  END wbs_adr_i[20]
  PIN wbs_adr_i[21]
    DIRECTION INPUT ;
    PORT
      LAYER met2 ;
        RECT 175.810 0.000 176.090 4.000 ;
    END
  END wbs_adr_i[21]
  PIN wbs_adr_i[22]
    DIRECTION INPUT ;
    PORT
      LAYER met2 ;
        RECT 182.710 0.000 182.990 4.000 ;
    END
  END wbs_adr_i[22]
  PIN wbs_adr_i[23]
    DIRECTION INPUT ;
    PORT
      LAYER met2 ;
        RECT 190.070 0.000 190.350 4.000 ;
    END
  END wbs_adr_i[23]
  PIN wbs_adr_i[24]
    DIRECTION INPUT ;
    PORT
      LAYER met2 ;
        RECT 196.970 0.000 197.250 4.000 ;
    END
  END wbs_adr_i[24]
  PIN wbs_adr_i[25]
    DIRECTION INPUT ;
    PORT
      LAYER met2 ;
        RECT 204.330 0.000 204.610 4.000 ;
    END
  END wbs_adr_i[25]
  PIN wbs_adr_i[26]
    DIRECTION INPUT ;
    PORT
      LAYER met2 ;
        RECT 211.690 0.000 211.970 4.000 ;
    END
  END wbs_adr_i[26]
  PIN wbs_adr_i[27]
    DIRECTION INPUT ;
    PORT
      LAYER met2 ;
        RECT 218.590 0.000 218.870 4.000 ;
    END
  END wbs_adr_i[27]
  PIN wbs_adr_i[28]
    DIRECTION INPUT ;
    PORT
      LAYER met2 ;
        RECT 225.950 0.000 226.230 4.000 ;
    END
  END wbs_adr_i[28]
  PIN wbs_adr_i[29]
    DIRECTION INPUT ;
    PORT
      LAYER met2 ;
        RECT 232.850 0.000 233.130 4.000 ;
    END
  END wbs_adr_i[29]
  PIN wbs_adr_i[2]
    DIRECTION INPUT ;
    PORT
      LAYER met2 ;
        RECT 34.130 0.000 34.410 4.000 ;
    END
  END wbs_adr_i[2]
  PIN wbs_adr_i[30]
    DIRECTION INPUT ;
    PORT
      LAYER met2 ;
        RECT 240.210 0.000 240.490 4.000 ;
    END
  END wbs_adr_i[30]
  PIN wbs_adr_i[31]
    DIRECTION INPUT ;
    PORT
      LAYER met2 ;
        RECT 247.570 0.000 247.850 4.000 ;
    END
  END wbs_adr_i[31]
  PIN wbs_adr_i[3]
    DIRECTION INPUT ;
    PORT
      LAYER met2 ;
        RECT 43.790 0.000 44.070 4.000 ;
    END
  END wbs_adr_i[3]
  PIN wbs_adr_i[4]
    DIRECTION INPUT ;
    PORT
      LAYER met2 ;
        RECT 53.450 0.000 53.730 4.000 ;
    END
  END wbs_adr_i[4]
  PIN wbs_adr_i[5]
    DIRECTION INPUT ;
    PORT
      LAYER met2 ;
        RECT 60.810 0.000 61.090 4.000 ;
    END
  END wbs_adr_i[5]
  PIN wbs_adr_i[6]
    DIRECTION INPUT ;
    PORT
      LAYER met2 ;
        RECT 67.710 0.000 67.990 4.000 ;
    END
  END wbs_adr_i[6]
  PIN wbs_adr_i[7]
    DIRECTION INPUT ;
    PORT
      LAYER met2 ;
        RECT 75.070 0.000 75.350 4.000 ;
    END
  END wbs_adr_i[7]
  PIN wbs_adr_i[8]
    DIRECTION INPUT ;
    PORT
      LAYER met2 ;
        RECT 82.430 0.000 82.710 4.000 ;
    END
  END wbs_adr_i[8]
  PIN wbs_adr_i[9]
    DIRECTION INPUT ;
    PORT
      LAYER met2 ;
        RECT 89.330 0.000 89.610 4.000 ;
    END
  END wbs_adr_i[9]
  PIN wbs_cyc_i
    DIRECTION INPUT ;
    PORT
      LAYER met2 ;
        RECT 7.910 0.000 8.190 4.000 ;
    END
  END wbs_cyc_i
  PIN wbs_dat_i[0]
    DIRECTION INPUT ;
    PORT
      LAYER met2 ;
        RECT 17.570 0.000 17.850 4.000 ;
    END
  END wbs_dat_i[0]
  PIN wbs_dat_i[10]
    DIRECTION INPUT ;
    PORT
      LAYER met2 ;
        RECT 98.990 0.000 99.270 4.000 ;
    END
  END wbs_dat_i[10]
  PIN wbs_dat_i[11]
    DIRECTION INPUT ;
    PORT
      LAYER met2 ;
        RECT 106.350 0.000 106.630 4.000 ;
    END
  END wbs_dat_i[11]
  PIN wbs_dat_i[12]
    DIRECTION INPUT ;
    PORT
      LAYER met2 ;
        RECT 113.250 0.000 113.530 4.000 ;
    END
  END wbs_dat_i[12]
  PIN wbs_dat_i[13]
    DIRECTION INPUT ;
    PORT
      LAYER met2 ;
        RECT 120.610 0.000 120.890 4.000 ;
    END
  END wbs_dat_i[13]
  PIN wbs_dat_i[14]
    DIRECTION INPUT ;
    PORT
      LAYER met2 ;
        RECT 127.510 0.000 127.790 4.000 ;
    END
  END wbs_dat_i[14]
  PIN wbs_dat_i[15]
    DIRECTION INPUT ;
    PORT
      LAYER met2 ;
        RECT 134.870 0.000 135.150 4.000 ;
    END
  END wbs_dat_i[15]
  PIN wbs_dat_i[16]
    DIRECTION INPUT ;
    PORT
      LAYER met2 ;
        RECT 142.230 0.000 142.510 4.000 ;
    END
  END wbs_dat_i[16]
  PIN wbs_dat_i[17]
    DIRECTION INPUT ;
    PORT
      LAYER met2 ;
        RECT 149.130 0.000 149.410 4.000 ;
    END
  END wbs_dat_i[17]
  PIN wbs_dat_i[18]
    DIRECTION INPUT ;
    PORT
      LAYER met2 ;
        RECT 156.490 0.000 156.770 4.000 ;
    END
  END wbs_dat_i[18]
  PIN wbs_dat_i[19]
    DIRECTION INPUT ;
    PORT
      LAYER met2 ;
        RECT 163.850 0.000 164.130 4.000 ;
    END
  END wbs_dat_i[19]
  PIN wbs_dat_i[1]
    DIRECTION INPUT ;
    PORT
      LAYER met2 ;
        RECT 27.230 0.000 27.510 4.000 ;
    END
  END wbs_dat_i[1]
  PIN wbs_dat_i[20]
    DIRECTION INPUT ;
    PORT
      LAYER met2 ;
        RECT 170.750 0.000 171.030 4.000 ;
    END
  END wbs_dat_i[20]
  PIN wbs_dat_i[21]
    DIRECTION INPUT ;
    PORT
      LAYER met2 ;
        RECT 178.110 0.000 178.390 4.000 ;
    END
  END wbs_dat_i[21]
  PIN wbs_dat_i[22]
    DIRECTION INPUT ;
    PORT
      LAYER met2 ;
        RECT 185.010 0.000 185.290 4.000 ;
    END
  END wbs_dat_i[22]
  PIN wbs_dat_i[23]
    DIRECTION INPUT ;
    PORT
      LAYER met2 ;
        RECT 192.370 0.000 192.650 4.000 ;
    END
  END wbs_dat_i[23]
  PIN wbs_dat_i[24]
    DIRECTION INPUT ;
    PORT
      LAYER met2 ;
        RECT 199.730 0.000 200.010 4.000 ;
    END
  END wbs_dat_i[24]
  PIN wbs_dat_i[25]
    DIRECTION INPUT ;
    PORT
      LAYER met2 ;
        RECT 206.630 0.000 206.910 4.000 ;
    END
  END wbs_dat_i[25]
  PIN wbs_dat_i[26]
    DIRECTION INPUT ;
    PORT
      LAYER met2 ;
        RECT 213.990 0.000 214.270 4.000 ;
    END
  END wbs_dat_i[26]
  PIN wbs_dat_i[27]
    DIRECTION INPUT ;
    PORT
      LAYER met2 ;
        RECT 220.890 0.000 221.170 4.000 ;
    END
  END wbs_dat_i[27]
  PIN wbs_dat_i[28]
    DIRECTION INPUT ;
    PORT
      LAYER met2 ;
        RECT 228.250 0.000 228.530 4.000 ;
    END
  END wbs_dat_i[28]
  PIN wbs_dat_i[29]
    DIRECTION INPUT ;
    PORT
      LAYER met2 ;
        RECT 235.610 0.000 235.890 4.000 ;
    END
  END wbs_dat_i[29]
  PIN wbs_dat_i[2]
    DIRECTION INPUT ;
    PORT
      LAYER met2 ;
        RECT 36.890 0.000 37.170 4.000 ;
    END
  END wbs_dat_i[2]
  PIN wbs_dat_i[30]
    DIRECTION INPUT ;
    PORT
      LAYER met2 ;
        RECT 242.510 0.000 242.790 4.000 ;
    END
  END wbs_dat_i[30]
  PIN wbs_dat_i[31]
    DIRECTION INPUT ;
    PORT
      LAYER met2 ;
        RECT 249.870 0.000 250.150 4.000 ;
    END
  END wbs_dat_i[31]
  PIN wbs_dat_i[3]
    DIRECTION INPUT ;
    PORT
      LAYER met2 ;
        RECT 46.090 0.000 46.370 4.000 ;
    END
  END wbs_dat_i[3]
  PIN wbs_dat_i[4]
    DIRECTION INPUT ;
    PORT
      LAYER met2 ;
        RECT 55.750 0.000 56.030 4.000 ;
    END
  END wbs_dat_i[4]
  PIN wbs_dat_i[5]
    DIRECTION INPUT ;
    PORT
      LAYER met2 ;
        RECT 63.110 0.000 63.390 4.000 ;
    END
  END wbs_dat_i[5]
  PIN wbs_dat_i[6]
    DIRECTION INPUT ;
    PORT
      LAYER met2 ;
        RECT 70.010 0.000 70.290 4.000 ;
    END
  END wbs_dat_i[6]
  PIN wbs_dat_i[7]
    DIRECTION INPUT ;
    PORT
      LAYER met2 ;
        RECT 77.370 0.000 77.650 4.000 ;
    END
  END wbs_dat_i[7]
  PIN wbs_dat_i[8]
    DIRECTION INPUT ;
    PORT
      LAYER met2 ;
        RECT 84.730 0.000 85.010 4.000 ;
    END
  END wbs_dat_i[8]
  PIN wbs_dat_i[9]
    DIRECTION INPUT ;
    PORT
      LAYER met2 ;
        RECT 91.630 0.000 91.910 4.000 ;
    END
  END wbs_dat_i[9]
  PIN wbs_dat_o[0]
    DIRECTION OUTPUT TRISTATE ;
    PORT
      LAYER met2 ;
        RECT 19.870 0.000 20.150 4.000 ;
    END
  END wbs_dat_o[0]
  PIN wbs_dat_o[10]
    DIRECTION OUTPUT TRISTATE ;
    PORT
      LAYER met2 ;
        RECT 101.290 0.000 101.570 4.000 ;
    END
  END wbs_dat_o[10]
  PIN wbs_dat_o[11]
    DIRECTION OUTPUT TRISTATE ;
    PORT
      LAYER met2 ;
        RECT 108.650 0.000 108.930 4.000 ;
    END
  END wbs_dat_o[11]
  PIN wbs_dat_o[12]
    DIRECTION OUTPUT TRISTATE ;
    PORT
      LAYER met2 ;
        RECT 115.550 0.000 115.830 4.000 ;
    END
  END wbs_dat_o[12]
  PIN wbs_dat_o[13]
    DIRECTION OUTPUT TRISTATE ;
    PORT
      LAYER met2 ;
        RECT 122.910 0.000 123.190 4.000 ;
    END
  END wbs_dat_o[13]
  PIN wbs_dat_o[14]
    DIRECTION OUTPUT TRISTATE ;
    PORT
      LAYER met2 ;
        RECT 130.270 0.000 130.550 4.000 ;
    END
  END wbs_dat_o[14]
  PIN wbs_dat_o[15]
    DIRECTION OUTPUT TRISTATE ;
    PORT
      LAYER met2 ;
        RECT 137.170 0.000 137.450 4.000 ;
    END
  END wbs_dat_o[15]
  PIN wbs_dat_o[16]
    DIRECTION OUTPUT TRISTATE ;
    PORT
      LAYER met2 ;
        RECT 144.530 0.000 144.810 4.000 ;
    END
  END wbs_dat_o[16]
  PIN wbs_dat_o[17]
    DIRECTION OUTPUT TRISTATE ;
    PORT
      LAYER met2 ;
        RECT 151.430 0.000 151.710 4.000 ;
    END
  END wbs_dat_o[17]
  PIN wbs_dat_o[18]
    DIRECTION OUTPUT TRISTATE ;
    PORT
      LAYER met2 ;
        RECT 158.790 0.000 159.070 4.000 ;
    END
  END wbs_dat_o[18]
  PIN wbs_dat_o[19]
    DIRECTION OUTPUT TRISTATE ;
    PORT
      LAYER met2 ;
        RECT 166.150 0.000 166.430 4.000 ;
    END
  END wbs_dat_o[19]
  PIN wbs_dat_o[1]
    DIRECTION OUTPUT TRISTATE ;
    PORT
      LAYER met2 ;
        RECT 29.530 0.000 29.810 4.000 ;
    END
  END wbs_dat_o[1]
  PIN wbs_dat_o[20]
    DIRECTION OUTPUT TRISTATE ;
    PORT
      LAYER met2 ;
        RECT 173.050 0.000 173.330 4.000 ;
    END
  END wbs_dat_o[20]
  PIN wbs_dat_o[21]
    DIRECTION OUTPUT TRISTATE ;
    PORT
      LAYER met2 ;
        RECT 180.410 0.000 180.690 4.000 ;
    END
  END wbs_dat_o[21]
  PIN wbs_dat_o[22]
    DIRECTION OUTPUT TRISTATE ;
    PORT
      LAYER met2 ;
        RECT 187.770 0.000 188.050 4.000 ;
    END
  END wbs_dat_o[22]
  PIN wbs_dat_o[23]
    DIRECTION OUTPUT TRISTATE ;
    PORT
      LAYER met2 ;
        RECT 194.670 0.000 194.950 4.000 ;
    END
  END wbs_dat_o[23]
  PIN wbs_dat_o[24]
    DIRECTION OUTPUT TRISTATE ;
    PORT
      LAYER met2 ;
        RECT 202.030 0.000 202.310 4.000 ;
    END
  END wbs_dat_o[24]
  PIN wbs_dat_o[25]
    DIRECTION OUTPUT TRISTATE ;
    PORT
      LAYER met2 ;
        RECT 208.930 0.000 209.210 4.000 ;
    END
  END wbs_dat_o[25]
  PIN wbs_dat_o[26]
    DIRECTION OUTPUT TRISTATE ;
    PORT
      LAYER met2 ;
        RECT 216.290 0.000 216.570 4.000 ;
    END
  END wbs_dat_o[26]
  PIN wbs_dat_o[27]
    DIRECTION OUTPUT TRISTATE ;
    PORT
      LAYER met2 ;
        RECT 223.650 0.000 223.930 4.000 ;
    END
  END wbs_dat_o[27]
  PIN wbs_dat_o[28]
    DIRECTION OUTPUT TRISTATE ;
    PORT
      LAYER met2 ;
        RECT 230.550 0.000 230.830 4.000 ;
    END
  END wbs_dat_o[28]
  PIN wbs_dat_o[29]
    DIRECTION OUTPUT TRISTATE ;
    PORT
      LAYER met2 ;
        RECT 237.910 0.000 238.190 4.000 ;
    END
  END wbs_dat_o[29]
  PIN wbs_dat_o[2]
    DIRECTION OUTPUT TRISTATE ;
    PORT
      LAYER met2 ;
        RECT 39.190 0.000 39.470 4.000 ;
    END
  END wbs_dat_o[2]
  PIN wbs_dat_o[30]
    DIRECTION OUTPUT TRISTATE ;
    PORT
      LAYER met2 ;
        RECT 245.270 0.000 245.550 4.000 ;
    END
  END wbs_dat_o[30]
  PIN wbs_dat_o[31]
    DIRECTION OUTPUT TRISTATE ;
    PORT
      LAYER met2 ;
        RECT 252.170 0.000 252.450 4.000 ;
    END
  END wbs_dat_o[31]
  PIN wbs_dat_o[3]
    DIRECTION OUTPUT TRISTATE ;
    PORT
      LAYER met2 ;
        RECT 48.850 0.000 49.130 4.000 ;
    END
  END wbs_dat_o[3]
  PIN wbs_dat_o[4]
    DIRECTION OUTPUT TRISTATE ;
    PORT
      LAYER met2 ;
        RECT 58.050 0.000 58.330 4.000 ;
    END
  END wbs_dat_o[4]
  PIN wbs_dat_o[5]
    DIRECTION OUTPUT TRISTATE ;
    PORT
      LAYER met2 ;
        RECT 65.410 0.000 65.690 4.000 ;
    END
  END wbs_dat_o[5]
  PIN wbs_dat_o[6]
    DIRECTION OUTPUT TRISTATE ;
    PORT
      LAYER met2 ;
        RECT 72.770 0.000 73.050 4.000 ;
    END
  END wbs_dat_o[6]
  PIN wbs_dat_o[7]
    DIRECTION OUTPUT TRISTATE ;
    PORT
      LAYER met2 ;
        RECT 79.670 0.000 79.950 4.000 ;
    END
  END wbs_dat_o[7]
  PIN wbs_dat_o[8]
    DIRECTION OUTPUT TRISTATE ;
    PORT
      LAYER met2 ;
        RECT 87.030 0.000 87.310 4.000 ;
    END
  END wbs_dat_o[8]
  PIN wbs_dat_o[9]
    DIRECTION OUTPUT TRISTATE ;
    PORT
      LAYER met2 ;
        RECT 94.390 0.000 94.670 4.000 ;
    END
  END wbs_dat_o[9]
  PIN wbs_sel_i[0]
    DIRECTION INPUT ;
    PORT
      LAYER met2 ;
        RECT 22.170 0.000 22.450 4.000 ;
    END
  END wbs_sel_i[0]
  PIN wbs_sel_i[1]
    DIRECTION INPUT ;
    PORT
      LAYER met2 ;
        RECT 31.830 0.000 32.110 4.000 ;
    END
  END wbs_sel_i[1]
  PIN wbs_sel_i[2]
    DIRECTION INPUT ;
    PORT
      LAYER met2 ;
        RECT 41.490 0.000 41.770 4.000 ;
    END
  END wbs_sel_i[2]
  PIN wbs_sel_i[3]
    DIRECTION INPUT ;
    PORT
      LAYER met2 ;
        RECT 51.150 0.000 51.430 4.000 ;
    END
  END wbs_sel_i[3]
  PIN wbs_stb_i
    DIRECTION INPUT ;
    PORT
      LAYER met2 ;
        RECT 10.210 0.000 10.490 4.000 ;
    END
  END wbs_stb_i
  PIN wbs_we_i
    DIRECTION INPUT ;
    PORT
      LAYER met2 ;
        RECT 12.970 0.000 13.250 4.000 ;
    END
  END wbs_we_i
  PIN VPWR
    DIRECTION INPUT ;
    USE POWER ;
    PORT
      LAYER met4 ;
        RECT 21.040 10.640 22.640 1172.560 ;
    END
  END VPWR
  PIN VGND
    DIRECTION INPUT ;
    USE GROUND ;
    PORT
      LAYER met4 ;
        RECT 97.840 10.640 99.440 1172.560 ;
    END
  END VGND
  OBS
      LAYER li1 ;
        RECT 5.520 10.795 1167.480 1172.405 ;
      LAYER met1 ;
        RECT 0.990 5.480 1169.710 1172.560 ;
      LAYER met2 ;
        RECT 1.020 1179.730 21.430 1180.010 ;
        RECT 22.270 1179.730 64.670 1180.010 ;
        RECT 65.510 1179.730 107.910 1180.010 ;
        RECT 108.750 1179.730 151.610 1180.010 ;
        RECT 152.450 1179.730 194.850 1180.010 ;
        RECT 195.690 1179.730 238.550 1180.010 ;
        RECT 239.390 1179.730 281.790 1180.010 ;
        RECT 282.630 1179.730 325.490 1180.010 ;
        RECT 326.330 1179.730 368.730 1180.010 ;
        RECT 369.570 1179.730 412.430 1180.010 ;
        RECT 413.270 1179.730 455.670 1180.010 ;
        RECT 456.510 1179.730 499.370 1180.010 ;
        RECT 500.210 1179.730 542.610 1180.010 ;
        RECT 543.450 1179.730 586.310 1180.010 ;
        RECT 587.150 1179.730 629.550 1180.010 ;
        RECT 630.390 1179.730 673.250 1180.010 ;
        RECT 674.090 1179.730 716.490 1180.010 ;
        RECT 717.330 1179.730 760.190 1180.010 ;
        RECT 761.030 1179.730 803.430 1180.010 ;
        RECT 804.270 1179.730 847.130 1180.010 ;
        RECT 847.970 1179.730 890.370 1180.010 ;
        RECT 891.210 1179.730 934.070 1180.010 ;
        RECT 934.910 1179.730 977.310 1180.010 ;
        RECT 978.150 1179.730 1021.010 1180.010 ;
        RECT 1021.850 1179.730 1064.250 1180.010 ;
        RECT 1065.090 1179.730 1107.950 1180.010 ;
        RECT 1108.790 1179.730 1151.190 1180.010 ;
        RECT 1152.030 1179.730 1169.680 1180.010 ;
        RECT 1.020 4.280 1169.680 1179.730 ;
        RECT 1.570 4.000 3.030 4.280 ;
        RECT 3.870 4.000 5.330 4.280 ;
        RECT 6.170 4.000 7.630 4.280 ;
        RECT 8.470 4.000 9.930 4.280 ;
        RECT 10.770 4.000 12.690 4.280 ;
        RECT 13.530 4.000 14.990 4.280 ;
        RECT 15.830 4.000 17.290 4.280 ;
        RECT 18.130 4.000 19.590 4.280 ;
        RECT 20.430 4.000 21.890 4.280 ;
        RECT 22.730 4.000 24.650 4.280 ;
        RECT 25.490 4.000 26.950 4.280 ;
        RECT 27.790 4.000 29.250 4.280 ;
        RECT 30.090 4.000 31.550 4.280 ;
        RECT 32.390 4.000 33.850 4.280 ;
        RECT 34.690 4.000 36.610 4.280 ;
        RECT 37.450 4.000 38.910 4.280 ;
        RECT 39.750 4.000 41.210 4.280 ;
        RECT 42.050 4.000 43.510 4.280 ;
        RECT 44.350 4.000 45.810 4.280 ;
        RECT 46.650 4.000 48.570 4.280 ;
        RECT 49.410 4.000 50.870 4.280 ;
        RECT 51.710 4.000 53.170 4.280 ;
        RECT 54.010 4.000 55.470 4.280 ;
        RECT 56.310 4.000 57.770 4.280 ;
        RECT 58.610 4.000 60.530 4.280 ;
        RECT 61.370 4.000 62.830 4.280 ;
        RECT 63.670 4.000 65.130 4.280 ;
        RECT 65.970 4.000 67.430 4.280 ;
        RECT 68.270 4.000 69.730 4.280 ;
        RECT 70.570 4.000 72.490 4.280 ;
        RECT 73.330 4.000 74.790 4.280 ;
        RECT 75.630 4.000 77.090 4.280 ;
        RECT 77.930 4.000 79.390 4.280 ;
        RECT 80.230 4.000 82.150 4.280 ;
        RECT 82.990 4.000 84.450 4.280 ;
        RECT 85.290 4.000 86.750 4.280 ;
        RECT 87.590 4.000 89.050 4.280 ;
        RECT 89.890 4.000 91.350 4.280 ;
        RECT 92.190 4.000 94.110 4.280 ;
        RECT 94.950 4.000 96.410 4.280 ;
        RECT 97.250 4.000 98.710 4.280 ;
        RECT 99.550 4.000 101.010 4.280 ;
        RECT 101.850 4.000 103.310 4.280 ;
        RECT 104.150 4.000 106.070 4.280 ;
        RECT 106.910 4.000 108.370 4.280 ;
        RECT 109.210 4.000 110.670 4.280 ;
        RECT 111.510 4.000 112.970 4.280 ;
        RECT 113.810 4.000 115.270 4.280 ;
        RECT 116.110 4.000 118.030 4.280 ;
        RECT 118.870 4.000 120.330 4.280 ;
        RECT 121.170 4.000 122.630 4.280 ;
        RECT 123.470 4.000 124.930 4.280 ;
        RECT 125.770 4.000 127.230 4.280 ;
        RECT 128.070 4.000 129.990 4.280 ;
        RECT 130.830 4.000 132.290 4.280 ;
        RECT 133.130 4.000 134.590 4.280 ;
        RECT 135.430 4.000 136.890 4.280 ;
        RECT 137.730 4.000 139.190 4.280 ;
        RECT 140.030 4.000 141.950 4.280 ;
        RECT 142.790 4.000 144.250 4.280 ;
        RECT 145.090 4.000 146.550 4.280 ;
        RECT 147.390 4.000 148.850 4.280 ;
        RECT 149.690 4.000 151.150 4.280 ;
        RECT 151.990 4.000 153.910 4.280 ;
        RECT 154.750 4.000 156.210 4.280 ;
        RECT 157.050 4.000 158.510 4.280 ;
        RECT 159.350 4.000 160.810 4.280 ;
        RECT 161.650 4.000 163.570 4.280 ;
        RECT 164.410 4.000 165.870 4.280 ;
        RECT 166.710 4.000 168.170 4.280 ;
        RECT 169.010 4.000 170.470 4.280 ;
        RECT 171.310 4.000 172.770 4.280 ;
        RECT 173.610 4.000 175.530 4.280 ;
        RECT 176.370 4.000 177.830 4.280 ;
        RECT 178.670 4.000 180.130 4.280 ;
        RECT 180.970 4.000 182.430 4.280 ;
        RECT 183.270 4.000 184.730 4.280 ;
        RECT 185.570 4.000 187.490 4.280 ;
        RECT 188.330 4.000 189.790 4.280 ;
        RECT 190.630 4.000 192.090 4.280 ;
        RECT 192.930 4.000 194.390 4.280 ;
        RECT 195.230 4.000 196.690 4.280 ;
        RECT 197.530 4.000 199.450 4.280 ;
        RECT 200.290 4.000 201.750 4.280 ;
        RECT 202.590 4.000 204.050 4.280 ;
        RECT 204.890 4.000 206.350 4.280 ;
        RECT 207.190 4.000 208.650 4.280 ;
        RECT 209.490 4.000 211.410 4.280 ;
        RECT 212.250 4.000 213.710 4.280 ;
        RECT 214.550 4.000 216.010 4.280 ;
        RECT 216.850 4.000 218.310 4.280 ;
        RECT 219.150 4.000 220.610 4.280 ;
        RECT 221.450 4.000 223.370 4.280 ;
        RECT 224.210 4.000 225.670 4.280 ;
        RECT 226.510 4.000 227.970 4.280 ;
        RECT 228.810 4.000 230.270 4.280 ;
        RECT 231.110 4.000 232.570 4.280 ;
        RECT 233.410 4.000 235.330 4.280 ;
        RECT 236.170 4.000 237.630 4.280 ;
        RECT 238.470 4.000 239.930 4.280 ;
        RECT 240.770 4.000 242.230 4.280 ;
        RECT 243.070 4.000 244.990 4.280 ;
        RECT 245.830 4.000 247.290 4.280 ;
        RECT 248.130 4.000 249.590 4.280 ;
        RECT 250.430 4.000 251.890 4.280 ;
        RECT 252.730 4.000 254.190 4.280 ;
        RECT 255.030 4.000 256.950 4.280 ;
        RECT 257.790 4.000 259.250 4.280 ;
        RECT 260.090 4.000 261.550 4.280 ;
        RECT 262.390 4.000 263.850 4.280 ;
        RECT 264.690 4.000 266.150 4.280 ;
        RECT 266.990 4.000 268.910 4.280 ;
        RECT 269.750 4.000 271.210 4.280 ;
        RECT 272.050 4.000 273.510 4.280 ;
        RECT 274.350 4.000 275.810 4.280 ;
        RECT 276.650 4.000 278.110 4.280 ;
        RECT 278.950 4.000 280.870 4.280 ;
        RECT 281.710 4.000 283.170 4.280 ;
        RECT 284.010 4.000 285.470 4.280 ;
        RECT 286.310 4.000 287.770 4.280 ;
        RECT 288.610 4.000 290.070 4.280 ;
        RECT 290.910 4.000 292.830 4.280 ;
        RECT 293.670 4.000 295.130 4.280 ;
        RECT 295.970 4.000 297.430 4.280 ;
        RECT 298.270 4.000 299.730 4.280 ;
        RECT 300.570 4.000 302.030 4.280 ;
        RECT 302.870 4.000 304.790 4.280 ;
        RECT 305.630 4.000 307.090 4.280 ;
        RECT 307.930 4.000 309.390 4.280 ;
        RECT 310.230 4.000 311.690 4.280 ;
        RECT 312.530 4.000 314.450 4.280 ;
        RECT 315.290 4.000 316.750 4.280 ;
        RECT 317.590 4.000 319.050 4.280 ;
        RECT 319.890 4.000 321.350 4.280 ;
        RECT 322.190 4.000 323.650 4.280 ;
        RECT 324.490 4.000 326.410 4.280 ;
        RECT 327.250 4.000 328.710 4.280 ;
        RECT 329.550 4.000 331.010 4.280 ;
        RECT 331.850 4.000 333.310 4.280 ;
        RECT 334.150 4.000 335.610 4.280 ;
        RECT 336.450 4.000 338.370 4.280 ;
        RECT 339.210 4.000 340.670 4.280 ;
        RECT 341.510 4.000 342.970 4.280 ;
        RECT 343.810 4.000 345.270 4.280 ;
        RECT 346.110 4.000 347.570 4.280 ;
        RECT 348.410 4.000 350.330 4.280 ;
        RECT 351.170 4.000 352.630 4.280 ;
        RECT 353.470 4.000 354.930 4.280 ;
        RECT 355.770 4.000 357.230 4.280 ;
        RECT 358.070 4.000 359.530 4.280 ;
        RECT 360.370 4.000 362.290 4.280 ;
        RECT 363.130 4.000 364.590 4.280 ;
        RECT 365.430 4.000 366.890 4.280 ;
        RECT 367.730 4.000 369.190 4.280 ;
        RECT 370.030 4.000 371.490 4.280 ;
        RECT 372.330 4.000 374.250 4.280 ;
        RECT 375.090 4.000 376.550 4.280 ;
        RECT 377.390 4.000 378.850 4.280 ;
        RECT 379.690 4.000 381.150 4.280 ;
        RECT 381.990 4.000 383.450 4.280 ;
        RECT 384.290 4.000 386.210 4.280 ;
        RECT 387.050 4.000 388.510 4.280 ;
        RECT 389.350 4.000 390.810 4.280 ;
        RECT 391.650 4.000 393.110 4.280 ;
        RECT 393.950 4.000 395.870 4.280 ;
        RECT 396.710 4.000 398.170 4.280 ;
        RECT 399.010 4.000 400.470 4.280 ;
        RECT 401.310 4.000 402.770 4.280 ;
        RECT 403.610 4.000 405.070 4.280 ;
        RECT 405.910 4.000 407.830 4.280 ;
        RECT 408.670 4.000 410.130 4.280 ;
        RECT 410.970 4.000 412.430 4.280 ;
        RECT 413.270 4.000 414.730 4.280 ;
        RECT 415.570 4.000 417.030 4.280 ;
        RECT 417.870 4.000 419.790 4.280 ;
        RECT 420.630 4.000 422.090 4.280 ;
        RECT 422.930 4.000 424.390 4.280 ;
        RECT 425.230 4.000 426.690 4.280 ;
        RECT 427.530 4.000 428.990 4.280 ;
        RECT 429.830 4.000 431.750 4.280 ;
        RECT 432.590 4.000 434.050 4.280 ;
        RECT 434.890 4.000 436.350 4.280 ;
        RECT 437.190 4.000 438.650 4.280 ;
        RECT 439.490 4.000 440.950 4.280 ;
        RECT 441.790 4.000 443.710 4.280 ;
        RECT 444.550 4.000 446.010 4.280 ;
        RECT 446.850 4.000 448.310 4.280 ;
        RECT 449.150 4.000 450.610 4.280 ;
        RECT 451.450 4.000 452.910 4.280 ;
        RECT 453.750 4.000 455.670 4.280 ;
        RECT 456.510 4.000 457.970 4.280 ;
        RECT 458.810 4.000 460.270 4.280 ;
        RECT 461.110 4.000 462.570 4.280 ;
        RECT 463.410 4.000 464.870 4.280 ;
        RECT 465.710 4.000 467.630 4.280 ;
        RECT 468.470 4.000 469.930 4.280 ;
        RECT 470.770 4.000 472.230 4.280 ;
        RECT 473.070 4.000 474.530 4.280 ;
        RECT 475.370 4.000 477.290 4.280 ;
        RECT 478.130 4.000 479.590 4.280 ;
        RECT 480.430 4.000 481.890 4.280 ;
        RECT 482.730 4.000 484.190 4.280 ;
        RECT 485.030 4.000 486.490 4.280 ;
        RECT 487.330 4.000 489.250 4.280 ;
        RECT 490.090 4.000 491.550 4.280 ;
        RECT 492.390 4.000 493.850 4.280 ;
        RECT 494.690 4.000 496.150 4.280 ;
        RECT 496.990 4.000 498.450 4.280 ;
        RECT 499.290 4.000 501.210 4.280 ;
        RECT 502.050 4.000 503.510 4.280 ;
        RECT 504.350 4.000 505.810 4.280 ;
        RECT 506.650 4.000 508.110 4.280 ;
        RECT 508.950 4.000 510.410 4.280 ;
        RECT 511.250 4.000 513.170 4.280 ;
        RECT 514.010 4.000 515.470 4.280 ;
        RECT 516.310 4.000 517.770 4.280 ;
        RECT 518.610 4.000 520.070 4.280 ;
        RECT 520.910 4.000 522.370 4.280 ;
        RECT 523.210 4.000 525.130 4.280 ;
        RECT 525.970 4.000 527.430 4.280 ;
        RECT 528.270 4.000 529.730 4.280 ;
        RECT 530.570 4.000 532.030 4.280 ;
        RECT 532.870 4.000 534.330 4.280 ;
        RECT 535.170 4.000 537.090 4.280 ;
        RECT 537.930 4.000 539.390 4.280 ;
        RECT 540.230 4.000 541.690 4.280 ;
        RECT 542.530 4.000 543.990 4.280 ;
        RECT 544.830 4.000 546.290 4.280 ;
        RECT 547.130 4.000 549.050 4.280 ;
        RECT 549.890 4.000 551.350 4.280 ;
        RECT 552.190 4.000 553.650 4.280 ;
        RECT 554.490 4.000 555.950 4.280 ;
        RECT 556.790 4.000 558.710 4.280 ;
        RECT 559.550 4.000 561.010 4.280 ;
        RECT 561.850 4.000 563.310 4.280 ;
        RECT 564.150 4.000 565.610 4.280 ;
        RECT 566.450 4.000 567.910 4.280 ;
        RECT 568.750 4.000 570.670 4.280 ;
        RECT 571.510 4.000 572.970 4.280 ;
        RECT 573.810 4.000 575.270 4.280 ;
        RECT 576.110 4.000 577.570 4.280 ;
        RECT 578.410 4.000 579.870 4.280 ;
        RECT 580.710 4.000 582.630 4.280 ;
        RECT 583.470 4.000 584.930 4.280 ;
        RECT 585.770 4.000 587.230 4.280 ;
        RECT 588.070 4.000 589.530 4.280 ;
        RECT 590.370 4.000 591.830 4.280 ;
        RECT 592.670 4.000 594.590 4.280 ;
        RECT 595.430 4.000 596.890 4.280 ;
        RECT 597.730 4.000 599.190 4.280 ;
        RECT 600.030 4.000 601.490 4.280 ;
        RECT 602.330 4.000 603.790 4.280 ;
        RECT 604.630 4.000 606.550 4.280 ;
        RECT 607.390 4.000 608.850 4.280 ;
        RECT 609.690 4.000 611.150 4.280 ;
        RECT 611.990 4.000 613.450 4.280 ;
        RECT 614.290 4.000 615.750 4.280 ;
        RECT 616.590 4.000 618.510 4.280 ;
        RECT 619.350 4.000 620.810 4.280 ;
        RECT 621.650 4.000 623.110 4.280 ;
        RECT 623.950 4.000 625.410 4.280 ;
        RECT 626.250 4.000 628.170 4.280 ;
        RECT 629.010 4.000 630.470 4.280 ;
        RECT 631.310 4.000 632.770 4.280 ;
        RECT 633.610 4.000 635.070 4.280 ;
        RECT 635.910 4.000 637.370 4.280 ;
        RECT 638.210 4.000 640.130 4.280 ;
        RECT 640.970 4.000 642.430 4.280 ;
        RECT 643.270 4.000 644.730 4.280 ;
        RECT 645.570 4.000 647.030 4.280 ;
        RECT 647.870 4.000 649.330 4.280 ;
        RECT 650.170 4.000 652.090 4.280 ;
        RECT 652.930 4.000 654.390 4.280 ;
        RECT 655.230 4.000 656.690 4.280 ;
        RECT 657.530 4.000 658.990 4.280 ;
        RECT 659.830 4.000 661.290 4.280 ;
        RECT 662.130 4.000 664.050 4.280 ;
        RECT 664.890 4.000 666.350 4.280 ;
        RECT 667.190 4.000 668.650 4.280 ;
        RECT 669.490 4.000 670.950 4.280 ;
        RECT 671.790 4.000 673.250 4.280 ;
        RECT 674.090 4.000 676.010 4.280 ;
        RECT 676.850 4.000 678.310 4.280 ;
        RECT 679.150 4.000 680.610 4.280 ;
        RECT 681.450 4.000 682.910 4.280 ;
        RECT 683.750 4.000 685.210 4.280 ;
        RECT 686.050 4.000 687.970 4.280 ;
        RECT 688.810 4.000 690.270 4.280 ;
        RECT 691.110 4.000 692.570 4.280 ;
        RECT 693.410 4.000 694.870 4.280 ;
        RECT 695.710 4.000 697.170 4.280 ;
        RECT 698.010 4.000 699.930 4.280 ;
        RECT 700.770 4.000 702.230 4.280 ;
        RECT 703.070 4.000 704.530 4.280 ;
        RECT 705.370 4.000 706.830 4.280 ;
        RECT 707.670 4.000 709.590 4.280 ;
        RECT 710.430 4.000 711.890 4.280 ;
        RECT 712.730 4.000 714.190 4.280 ;
        RECT 715.030 4.000 716.490 4.280 ;
        RECT 717.330 4.000 718.790 4.280 ;
        RECT 719.630 4.000 721.550 4.280 ;
        RECT 722.390 4.000 723.850 4.280 ;
        RECT 724.690 4.000 726.150 4.280 ;
        RECT 726.990 4.000 728.450 4.280 ;
        RECT 729.290 4.000 730.750 4.280 ;
        RECT 731.590 4.000 733.510 4.280 ;
        RECT 734.350 4.000 735.810 4.280 ;
        RECT 736.650 4.000 738.110 4.280 ;
        RECT 738.950 4.000 740.410 4.280 ;
        RECT 741.250 4.000 742.710 4.280 ;
        RECT 743.550 4.000 745.470 4.280 ;
        RECT 746.310 4.000 747.770 4.280 ;
        RECT 748.610 4.000 750.070 4.280 ;
        RECT 750.910 4.000 752.370 4.280 ;
        RECT 753.210 4.000 754.670 4.280 ;
        RECT 755.510 4.000 757.430 4.280 ;
        RECT 758.270 4.000 759.730 4.280 ;
        RECT 760.570 4.000 762.030 4.280 ;
        RECT 762.870 4.000 764.330 4.280 ;
        RECT 765.170 4.000 766.630 4.280 ;
        RECT 767.470 4.000 769.390 4.280 ;
        RECT 770.230 4.000 771.690 4.280 ;
        RECT 772.530 4.000 773.990 4.280 ;
        RECT 774.830 4.000 776.290 4.280 ;
        RECT 777.130 4.000 778.590 4.280 ;
        RECT 779.430 4.000 781.350 4.280 ;
        RECT 782.190 4.000 783.650 4.280 ;
        RECT 784.490 4.000 785.950 4.280 ;
        RECT 786.790 4.000 788.250 4.280 ;
        RECT 789.090 4.000 791.010 4.280 ;
        RECT 791.850 4.000 793.310 4.280 ;
        RECT 794.150 4.000 795.610 4.280 ;
        RECT 796.450 4.000 797.910 4.280 ;
        RECT 798.750 4.000 800.210 4.280 ;
        RECT 801.050 4.000 802.970 4.280 ;
        RECT 803.810 4.000 805.270 4.280 ;
        RECT 806.110 4.000 807.570 4.280 ;
        RECT 808.410 4.000 809.870 4.280 ;
        RECT 810.710 4.000 812.170 4.280 ;
        RECT 813.010 4.000 814.930 4.280 ;
        RECT 815.770 4.000 817.230 4.280 ;
        RECT 818.070 4.000 819.530 4.280 ;
        RECT 820.370 4.000 821.830 4.280 ;
        RECT 822.670 4.000 824.130 4.280 ;
        RECT 824.970 4.000 826.890 4.280 ;
        RECT 827.730 4.000 829.190 4.280 ;
        RECT 830.030 4.000 831.490 4.280 ;
        RECT 832.330 4.000 833.790 4.280 ;
        RECT 834.630 4.000 836.090 4.280 ;
        RECT 836.930 4.000 838.850 4.280 ;
        RECT 839.690 4.000 841.150 4.280 ;
        RECT 841.990 4.000 843.450 4.280 ;
        RECT 844.290 4.000 845.750 4.280 ;
        RECT 846.590 4.000 848.050 4.280 ;
        RECT 848.890 4.000 850.810 4.280 ;
        RECT 851.650 4.000 853.110 4.280 ;
        RECT 853.950 4.000 855.410 4.280 ;
        RECT 856.250 4.000 857.710 4.280 ;
        RECT 858.550 4.000 860.010 4.280 ;
        RECT 860.850 4.000 862.770 4.280 ;
        RECT 863.610 4.000 865.070 4.280 ;
        RECT 865.910 4.000 867.370 4.280 ;
        RECT 868.210 4.000 869.670 4.280 ;
        RECT 870.510 4.000 872.430 4.280 ;
        RECT 873.270 4.000 874.730 4.280 ;
        RECT 875.570 4.000 877.030 4.280 ;
        RECT 877.870 4.000 879.330 4.280 ;
        RECT 880.170 4.000 881.630 4.280 ;
        RECT 882.470 4.000 884.390 4.280 ;
        RECT 885.230 4.000 886.690 4.280 ;
        RECT 887.530 4.000 888.990 4.280 ;
        RECT 889.830 4.000 891.290 4.280 ;
        RECT 892.130 4.000 893.590 4.280 ;
        RECT 894.430 4.000 896.350 4.280 ;
        RECT 897.190 4.000 898.650 4.280 ;
        RECT 899.490 4.000 900.950 4.280 ;
        RECT 901.790 4.000 903.250 4.280 ;
        RECT 904.090 4.000 905.550 4.280 ;
        RECT 906.390 4.000 908.310 4.280 ;
        RECT 909.150 4.000 910.610 4.280 ;
        RECT 911.450 4.000 912.910 4.280 ;
        RECT 913.750 4.000 915.210 4.280 ;
        RECT 916.050 4.000 917.510 4.280 ;
        RECT 918.350 4.000 920.270 4.280 ;
        RECT 921.110 4.000 922.570 4.280 ;
        RECT 923.410 4.000 924.870 4.280 ;
        RECT 925.710 4.000 927.170 4.280 ;
        RECT 928.010 4.000 929.470 4.280 ;
        RECT 930.310 4.000 932.230 4.280 ;
        RECT 933.070 4.000 934.530 4.280 ;
        RECT 935.370 4.000 936.830 4.280 ;
        RECT 937.670 4.000 939.130 4.280 ;
        RECT 939.970 4.000 941.890 4.280 ;
        RECT 942.730 4.000 944.190 4.280 ;
        RECT 945.030 4.000 946.490 4.280 ;
        RECT 947.330 4.000 948.790 4.280 ;
        RECT 949.630 4.000 951.090 4.280 ;
        RECT 951.930 4.000 953.850 4.280 ;
        RECT 954.690 4.000 956.150 4.280 ;
        RECT 956.990 4.000 958.450 4.280 ;
        RECT 959.290 4.000 960.750 4.280 ;
        RECT 961.590 4.000 963.050 4.280 ;
        RECT 963.890 4.000 965.810 4.280 ;
        RECT 966.650 4.000 968.110 4.280 ;
        RECT 968.950 4.000 970.410 4.280 ;
        RECT 971.250 4.000 972.710 4.280 ;
        RECT 973.550 4.000 975.010 4.280 ;
        RECT 975.850 4.000 977.770 4.280 ;
        RECT 978.610 4.000 980.070 4.280 ;
        RECT 980.910 4.000 982.370 4.280 ;
        RECT 983.210 4.000 984.670 4.280 ;
        RECT 985.510 4.000 986.970 4.280 ;
        RECT 987.810 4.000 989.730 4.280 ;
        RECT 990.570 4.000 992.030 4.280 ;
        RECT 992.870 4.000 994.330 4.280 ;
        RECT 995.170 4.000 996.630 4.280 ;
        RECT 997.470 4.000 998.930 4.280 ;
        RECT 999.770 4.000 1001.690 4.280 ;
        RECT 1002.530 4.000 1003.990 4.280 ;
        RECT 1004.830 4.000 1006.290 4.280 ;
        RECT 1007.130 4.000 1008.590 4.280 ;
        RECT 1009.430 4.000 1010.890 4.280 ;
        RECT 1011.730 4.000 1013.650 4.280 ;
        RECT 1014.490 4.000 1015.950 4.280 ;
        RECT 1016.790 4.000 1018.250 4.280 ;
        RECT 1019.090 4.000 1020.550 4.280 ;
        RECT 1021.390 4.000 1023.310 4.280 ;
        RECT 1024.150 4.000 1025.610 4.280 ;
        RECT 1026.450 4.000 1027.910 4.280 ;
        RECT 1028.750 4.000 1030.210 4.280 ;
        RECT 1031.050 4.000 1032.510 4.280 ;
        RECT 1033.350 4.000 1035.270 4.280 ;
        RECT 1036.110 4.000 1037.570 4.280 ;
        RECT 1038.410 4.000 1039.870 4.280 ;
        RECT 1040.710 4.000 1042.170 4.280 ;
        RECT 1043.010 4.000 1044.470 4.280 ;
        RECT 1045.310 4.000 1047.230 4.280 ;
        RECT 1048.070 4.000 1049.530 4.280 ;
        RECT 1050.370 4.000 1051.830 4.280 ;
        RECT 1052.670 4.000 1054.130 4.280 ;
        RECT 1054.970 4.000 1056.430 4.280 ;
        RECT 1057.270 4.000 1059.190 4.280 ;
        RECT 1060.030 4.000 1061.490 4.280 ;
        RECT 1062.330 4.000 1063.790 4.280 ;
        RECT 1064.630 4.000 1066.090 4.280 ;
        RECT 1066.930 4.000 1068.390 4.280 ;
        RECT 1069.230 4.000 1071.150 4.280 ;
        RECT 1071.990 4.000 1073.450 4.280 ;
        RECT 1074.290 4.000 1075.750 4.280 ;
        RECT 1076.590 4.000 1078.050 4.280 ;
        RECT 1078.890 4.000 1080.350 4.280 ;
        RECT 1081.190 4.000 1083.110 4.280 ;
        RECT 1083.950 4.000 1085.410 4.280 ;
        RECT 1086.250 4.000 1087.710 4.280 ;
        RECT 1088.550 4.000 1090.010 4.280 ;
        RECT 1090.850 4.000 1092.310 4.280 ;
        RECT 1093.150 4.000 1095.070 4.280 ;
        RECT 1095.910 4.000 1097.370 4.280 ;
        RECT 1098.210 4.000 1099.670 4.280 ;
        RECT 1100.510 4.000 1101.970 4.280 ;
        RECT 1102.810 4.000 1104.730 4.280 ;
        RECT 1105.570 4.000 1107.030 4.280 ;
        RECT 1107.870 4.000 1109.330 4.280 ;
        RECT 1110.170 4.000 1111.630 4.280 ;
        RECT 1112.470 4.000 1113.930 4.280 ;
        RECT 1114.770 4.000 1116.690 4.280 ;
        RECT 1117.530 4.000 1118.990 4.280 ;
        RECT 1119.830 4.000 1121.290 4.280 ;
        RECT 1122.130 4.000 1123.590 4.280 ;
        RECT 1124.430 4.000 1125.890 4.280 ;
        RECT 1126.730 4.000 1128.650 4.280 ;
        RECT 1129.490 4.000 1130.950 4.280 ;
        RECT 1131.790 4.000 1133.250 4.280 ;
        RECT 1134.090 4.000 1135.550 4.280 ;
        RECT 1136.390 4.000 1137.850 4.280 ;
        RECT 1138.690 4.000 1140.610 4.280 ;
        RECT 1141.450 4.000 1142.910 4.280 ;
        RECT 1143.750 4.000 1145.210 4.280 ;
        RECT 1146.050 4.000 1147.510 4.280 ;
        RECT 1148.350 4.000 1149.810 4.280 ;
        RECT 1150.650 4.000 1152.570 4.280 ;
        RECT 1153.410 4.000 1154.870 4.280 ;
        RECT 1155.710 4.000 1157.170 4.280 ;
        RECT 1158.010 4.000 1159.470 4.280 ;
        RECT 1160.310 4.000 1161.770 4.280 ;
        RECT 1162.610 4.000 1164.530 4.280 ;
        RECT 1165.370 4.000 1166.830 4.280 ;
        RECT 1167.670 4.000 1169.130 4.280 ;
      LAYER met3 ;
        RECT 4.000 1171.320 1169.290 1172.485 ;
        RECT 4.000 1169.960 1168.890 1171.320 ;
        RECT 4.400 1169.920 1168.890 1169.960 ;
        RECT 4.400 1168.560 1169.290 1169.920 ;
        RECT 4.000 1144.800 1169.290 1168.560 ;
        RECT 4.000 1143.400 1168.890 1144.800 ;
        RECT 4.000 1142.080 1169.290 1143.400 ;
        RECT 4.400 1140.680 1169.290 1142.080 ;
        RECT 4.000 1118.280 1169.290 1140.680 ;
        RECT 4.000 1116.880 1168.890 1118.280 ;
        RECT 4.000 1113.520 1169.290 1116.880 ;
        RECT 4.400 1112.120 1169.290 1113.520 ;
        RECT 4.000 1092.440 1169.290 1112.120 ;
        RECT 4.000 1091.040 1168.890 1092.440 ;
        RECT 4.000 1085.640 1169.290 1091.040 ;
        RECT 4.400 1084.240 1169.290 1085.640 ;
        RECT 4.000 1065.920 1169.290 1084.240 ;
        RECT 4.000 1064.520 1168.890 1065.920 ;
        RECT 4.000 1057.080 1169.290 1064.520 ;
        RECT 4.400 1055.680 1169.290 1057.080 ;
        RECT 4.000 1039.400 1169.290 1055.680 ;
        RECT 4.000 1038.000 1168.890 1039.400 ;
        RECT 4.000 1029.200 1169.290 1038.000 ;
        RECT 4.400 1027.800 1169.290 1029.200 ;
        RECT 4.000 1013.560 1169.290 1027.800 ;
        RECT 4.000 1012.160 1168.890 1013.560 ;
        RECT 4.000 1000.640 1169.290 1012.160 ;
        RECT 4.400 999.240 1169.290 1000.640 ;
        RECT 4.000 987.040 1169.290 999.240 ;
        RECT 4.000 985.640 1168.890 987.040 ;
        RECT 4.000 972.760 1169.290 985.640 ;
        RECT 4.400 971.360 1169.290 972.760 ;
        RECT 4.000 960.520 1169.290 971.360 ;
        RECT 4.000 959.120 1168.890 960.520 ;
        RECT 4.000 944.200 1169.290 959.120 ;
        RECT 4.400 942.800 1169.290 944.200 ;
        RECT 4.000 934.680 1169.290 942.800 ;
        RECT 4.000 933.280 1168.890 934.680 ;
        RECT 4.000 916.320 1169.290 933.280 ;
        RECT 4.400 914.920 1169.290 916.320 ;
        RECT 4.000 908.160 1169.290 914.920 ;
        RECT 4.000 906.760 1168.890 908.160 ;
        RECT 4.000 888.440 1169.290 906.760 ;
        RECT 4.400 887.040 1169.290 888.440 ;
        RECT 4.000 881.640 1169.290 887.040 ;
        RECT 4.000 880.240 1168.890 881.640 ;
        RECT 4.000 859.880 1169.290 880.240 ;
        RECT 4.400 858.480 1169.290 859.880 ;
        RECT 4.000 855.800 1169.290 858.480 ;
        RECT 4.000 854.400 1168.890 855.800 ;
        RECT 4.000 832.000 1169.290 854.400 ;
        RECT 4.400 830.600 1169.290 832.000 ;
        RECT 4.000 829.280 1169.290 830.600 ;
        RECT 4.000 827.880 1168.890 829.280 ;
        RECT 4.000 803.440 1169.290 827.880 ;
        RECT 4.400 802.760 1169.290 803.440 ;
        RECT 4.400 802.040 1168.890 802.760 ;
        RECT 4.000 801.360 1168.890 802.040 ;
        RECT 4.000 776.240 1169.290 801.360 ;
        RECT 4.000 775.560 1168.890 776.240 ;
        RECT 4.400 774.840 1168.890 775.560 ;
        RECT 4.400 774.160 1169.290 774.840 ;
        RECT 4.000 750.400 1169.290 774.160 ;
        RECT 4.000 749.000 1168.890 750.400 ;
        RECT 4.000 747.000 1169.290 749.000 ;
        RECT 4.400 745.600 1169.290 747.000 ;
        RECT 4.000 723.880 1169.290 745.600 ;
        RECT 4.000 722.480 1168.890 723.880 ;
        RECT 4.000 719.120 1169.290 722.480 ;
        RECT 4.400 717.720 1169.290 719.120 ;
        RECT 4.000 697.360 1169.290 717.720 ;
        RECT 4.000 695.960 1168.890 697.360 ;
        RECT 4.000 690.560 1169.290 695.960 ;
        RECT 4.400 689.160 1169.290 690.560 ;
        RECT 4.000 671.520 1169.290 689.160 ;
        RECT 4.000 670.120 1168.890 671.520 ;
        RECT 4.000 662.680 1169.290 670.120 ;
        RECT 4.400 661.280 1169.290 662.680 ;
        RECT 4.000 645.000 1169.290 661.280 ;
        RECT 4.000 643.600 1168.890 645.000 ;
        RECT 4.000 634.120 1169.290 643.600 ;
        RECT 4.400 632.720 1169.290 634.120 ;
        RECT 4.000 618.480 1169.290 632.720 ;
        RECT 4.000 617.080 1168.890 618.480 ;
        RECT 4.000 606.240 1169.290 617.080 ;
        RECT 4.400 604.840 1169.290 606.240 ;
        RECT 4.000 592.640 1169.290 604.840 ;
        RECT 4.000 591.240 1168.890 592.640 ;
        RECT 4.000 578.360 1169.290 591.240 ;
        RECT 4.400 576.960 1169.290 578.360 ;
        RECT 4.000 566.120 1169.290 576.960 ;
        RECT 4.000 564.720 1168.890 566.120 ;
        RECT 4.000 549.800 1169.290 564.720 ;
        RECT 4.400 548.400 1169.290 549.800 ;
        RECT 4.000 539.600 1169.290 548.400 ;
        RECT 4.000 538.200 1168.890 539.600 ;
        RECT 4.000 521.920 1169.290 538.200 ;
        RECT 4.400 520.520 1169.290 521.920 ;
        RECT 4.000 513.760 1169.290 520.520 ;
        RECT 4.000 512.360 1168.890 513.760 ;
        RECT 4.000 493.360 1169.290 512.360 ;
        RECT 4.400 491.960 1169.290 493.360 ;
        RECT 4.000 487.240 1169.290 491.960 ;
        RECT 4.000 485.840 1168.890 487.240 ;
        RECT 4.000 465.480 1169.290 485.840 ;
        RECT 4.400 464.080 1169.290 465.480 ;
        RECT 4.000 460.720 1169.290 464.080 ;
        RECT 4.000 459.320 1168.890 460.720 ;
        RECT 4.000 436.920 1169.290 459.320 ;
        RECT 4.400 435.520 1169.290 436.920 ;
        RECT 4.000 434.880 1169.290 435.520 ;
        RECT 4.000 433.480 1168.890 434.880 ;
        RECT 4.000 409.040 1169.290 433.480 ;
        RECT 4.400 408.360 1169.290 409.040 ;
        RECT 4.400 407.640 1168.890 408.360 ;
        RECT 4.000 406.960 1168.890 407.640 ;
        RECT 4.000 381.840 1169.290 406.960 ;
        RECT 4.000 380.480 1168.890 381.840 ;
        RECT 4.400 380.440 1168.890 380.480 ;
        RECT 4.400 379.080 1169.290 380.440 ;
        RECT 4.000 355.320 1169.290 379.080 ;
        RECT 4.000 353.920 1168.890 355.320 ;
        RECT 4.000 352.600 1169.290 353.920 ;
        RECT 4.400 351.200 1169.290 352.600 ;
        RECT 4.000 329.480 1169.290 351.200 ;
        RECT 4.000 328.080 1168.890 329.480 ;
        RECT 4.000 324.040 1169.290 328.080 ;
        RECT 4.400 322.640 1169.290 324.040 ;
        RECT 4.000 302.960 1169.290 322.640 ;
        RECT 4.000 301.560 1168.890 302.960 ;
        RECT 4.000 296.160 1169.290 301.560 ;
        RECT 4.400 294.760 1169.290 296.160 ;
        RECT 4.000 276.440 1169.290 294.760 ;
        RECT 4.000 275.040 1168.890 276.440 ;
        RECT 4.000 268.280 1169.290 275.040 ;
        RECT 4.400 266.880 1169.290 268.280 ;
        RECT 4.000 250.600 1169.290 266.880 ;
        RECT 4.000 249.200 1168.890 250.600 ;
        RECT 4.000 239.720 1169.290 249.200 ;
        RECT 4.400 238.320 1169.290 239.720 ;
        RECT 4.000 224.080 1169.290 238.320 ;
        RECT 4.000 222.680 1168.890 224.080 ;
        RECT 4.000 211.840 1169.290 222.680 ;
        RECT 4.400 210.440 1169.290 211.840 ;
        RECT 4.000 197.560 1169.290 210.440 ;
        RECT 4.000 196.160 1168.890 197.560 ;
        RECT 4.000 183.280 1169.290 196.160 ;
        RECT 4.400 181.880 1169.290 183.280 ;
        RECT 4.000 171.720 1169.290 181.880 ;
        RECT 4.000 170.320 1168.890 171.720 ;
        RECT 4.000 155.400 1169.290 170.320 ;
        RECT 4.400 154.000 1169.290 155.400 ;
        RECT 4.000 145.200 1169.290 154.000 ;
        RECT 4.000 143.800 1168.890 145.200 ;
        RECT 4.000 126.840 1169.290 143.800 ;
        RECT 4.400 125.440 1169.290 126.840 ;
        RECT 4.000 118.680 1169.290 125.440 ;
        RECT 4.000 117.280 1168.890 118.680 ;
        RECT 4.000 98.960 1169.290 117.280 ;
        RECT 4.400 97.560 1169.290 98.960 ;
        RECT 4.000 92.840 1169.290 97.560 ;
        RECT 4.000 91.440 1168.890 92.840 ;
        RECT 4.000 70.400 1169.290 91.440 ;
        RECT 4.400 69.000 1169.290 70.400 ;
        RECT 4.000 66.320 1169.290 69.000 ;
        RECT 4.000 64.920 1168.890 66.320 ;
        RECT 4.000 42.520 1169.290 64.920 ;
        RECT 4.400 41.120 1169.290 42.520 ;
        RECT 4.000 39.800 1169.290 41.120 ;
        RECT 4.000 38.400 1168.890 39.800 ;
        RECT 4.000 14.640 1169.290 38.400 ;
        RECT 4.400 13.960 1169.290 14.640 ;
        RECT 4.400 13.240 1168.890 13.960 ;
        RECT 4.000 12.560 1168.890 13.240 ;
        RECT 4.000 10.715 1169.290 12.560 ;
      LAYER met4 ;
        RECT 26.975 10.640 97.440 1172.560 ;
        RECT 99.840 10.640 1097.840 1172.560 ;
  END
END accelerator_top
END LIBRARY

